# LEF file generated by Abstract Generator version 5.5.10 on Jul 28 14:07:14 2004
#
# Contains LEF for all bins.
# Options:   [x] Antenna
#            [x] Geometry
#            [x] Technology

VERSION 5.4 ;
NAMESCASESENSITIVE ON ;
BUSBITCHARS "[]" ;
DIVIDERCHAR "/" ;
UNITS
  DATABASE MICRONS 1000 ;
END UNITS

USEMINSPACING OBS ON ;
USEMINSPACING PIN OFF ;
CLEARANCEMEASURE EUCLIDEAN ;


MANUFACTURINGGRID 0.05 ;

LAYER nwell
  TYPE	MASTERSLICE ;
END nwell

LAYER nactive
  TYPE	MASTERSLICE ;
END nactive

LAYER pactive
  TYPE	MASTERSLICE ;
END pactive

LAYER poly
  TYPE	MASTERSLICE ;
END poly

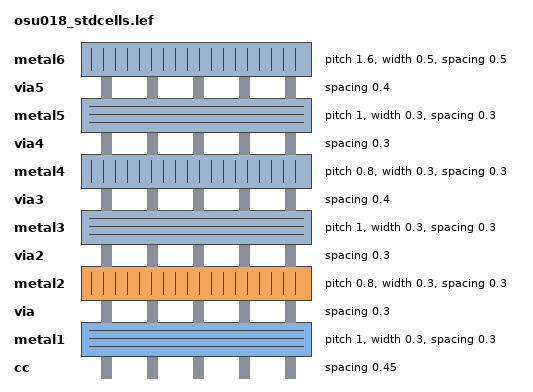
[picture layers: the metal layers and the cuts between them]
LAYER cc
  TYPE	CUT ;
  SPACING	0.45 ;
END cc

LAYER metal1
  TYPE		ROUTING ;
  DIRECTION	HORIZONTAL ;
  PITCH		1  ;
  OFFSET	0.5 ;
  WIDTH		0.3 ;
  SPACING	0.3 ;
  RESISTANCE	RPERSQ 0.08 ;
  CAPACITANCE	CPERSQDIST 3.8e-05 ;
  EDGECAPACITANCE 8.000000e-05 ;
END metal1

LAYER via
  TYPE	CUT ;
  SPACING	0.3 ;
END via

LAYER metal2
  TYPE		ROUTING ;
  DIRECTION	VERTICAL ;
  PITCH		0.8  ;
  OFFSET	0.4 ;
  WIDTH		0.3 ;
  SPACING	0.3 ;
  RESISTANCE	RPERSQ 0.08 ;
  CAPACITANCE	CPERSQDIST 1.9e-05 ;
  EDGECAPACITANCE 6.000000e-05 ;
END metal2

LAYER via2
  TYPE	CUT ;
  SPACING	0.3 ;
END via2

LAYER metal3
  TYPE		ROUTING ;
  DIRECTION	HORIZONTAL ;
  PITCH		1  ;
  OFFSET	0.5 ;
  WIDTH		0.3 ;
  SPACING	0.3 ;
  RESISTANCE	RPERSQ 0.08 ;
  CAPACITANCE	CPERSQDIST 1.3e-05 ;
  EDGECAPACITANCE 5.400000e-05 ;
END metal3

LAYER via3
  TYPE	CUT ;
  SPACING	0.4 ;
END via3

LAYER metal4
  TYPE		ROUTING ;
  DIRECTION	VERTICAL ;
  PITCH		0.8  ;
  OFFSET	0.4 ;
  WIDTH		0.3 ;
  SPACING	0.3 ;
  RESISTANCE	RPERSQ 0.07 ;
  CAPACITANCE	CPERSQDIST 8e-06 ;
  EDGECAPACITANCE 4.100000e-05 ;
END metal4

LAYER via4
  TYPE	CUT ;
  SPACING	0.3 ;
END via4

LAYER metal5
  TYPE		ROUTING ;
  DIRECTION	HORIZONTAL ;
  PITCH		1  ;
  OFFSET	0.5 ;
  WIDTH		0.3 ;
  SPACING	0.3 ;
  RESISTANCE	RPERSQ 0.07 ;
  CAPACITANCE	CPERSQDIST 8e-06 ;
  EDGECAPACITANCE 2.400000e-05 ;
END metal5

LAYER via5
  TYPE	CUT ;
  SPACING	0.4 ;
END via5

LAYER metal6
  TYPE		ROUTING ;
  DIRECTION	VERTICAL ;
  PITCH		1.6  ;
  OFFSET	0.8 ;
  WIDTH		0.5 ;
  SPACING	0.5 ;
  RESISTANCE	RPERSQ 0.03 ;
  CAPACITANCE	CPERSQDIST 3e-06 ;
  EDGECAPACITANCE 2.000000e-05 ;
END metal6

VIA M2_M1 DEFAULT
  LAYER metal1 ;
    RECT -0.200 -0.200 0.200 0.200 ;
  LAYER via ;
    RECT -0.100 -0.100 0.100 0.100 ;
  LAYER metal2 ;
    RECT -0.200 -0.200 0.200 0.200 ;
END M2_M1

VIA M3_M2 DEFAULT
  LAYER metal2 ;
    RECT -0.200 -0.200 0.200 0.200 ;
  LAYER via2 ;
    RECT -0.100 -0.100 0.100 0.100 ;
  LAYER metal3 ;
    RECT -0.200 -0.200 0.200 0.200 ;
END M3_M2

VIA M4_M3 DEFAULT
  LAYER metal3 ;
    RECT -0.200 -0.200 0.200 0.200 ;
  LAYER via3 ;
    RECT -0.100 -0.100 0.100 0.100 ;
  LAYER metal4 ;
    RECT -0.200 -0.200 0.200 0.200 ;
END M4_M3

VIA M5_M4 DEFAULT
  LAYER metal4 ;
    RECT -0.200 -0.200 0.200 0.200 ;
  LAYER via4 ;
    RECT -0.100 -0.100 0.100 0.100 ;
  LAYER metal5 ;
    RECT -0.200 -0.200 0.200 0.200 ;
END M5_M4

VIA M6_M5 DEFAULT
  LAYER metal5 ;
    RECT -0.25 -0.25 0.25 0.25 ;
  LAYER via5 ;
    RECT -0.15 -0.15 0.15 0.15 ;
  LAYER metal6 ;
    RECT -0.25 -0.25 0.25 0.25 ;
END M6_M5


VIARULE viagen21 GENERATE
  LAYER metal1 ;
    DIRECTION HORIZONTAL ;
    WIDTH 0.3 TO 60 ;
    OVERHANG 0.1 ;
    METALOVERHANG 0 ;
  LAYER metal2 ;
    DIRECTION VERTICAL ;
    WIDTH 0.3 TO 60 ;
    OVERHANG 0.1 ;
    METALOVERHANG 0 ;
  LAYER via ;
    RECT -0.1 -0.1 0.1 0.1 ;
    SPACING 0.5 BY 0.5 ;
END viagen21

VIARULE viagen32 GENERATE
  LAYER metal3 ;
    DIRECTION HORIZONTAL ;
    WIDTH 0.3 TO 60 ;
    OVERHANG 0.1 ;
    METALOVERHANG 0 ;
  LAYER metal2 ;
    DIRECTION VERTICAL ;
    WIDTH 0.3 TO 60 ;
    OVERHANG 0.1 ;
    METALOVERHANG 0 ;
  LAYER via2 ;
    RECT -0.1 -0.1 0.1 0.1 ;
    SPACING 0.5 BY 0.5 ;
END viagen32

VIARULE viagen43 GENERATE
  LAYER metal3 ;
    DIRECTION HORIZONTAL ;
    WIDTH 0.3 TO 60 ;
    OVERHANG 0.1 ;
    METALOVERHANG 0 ;
  LAYER metal4 ;
    DIRECTION VERTICAL ;
    WIDTH 0.3 TO 60 ;
    OVERHANG 0.1 ;
    METALOVERHANG 0 ;
  LAYER via3 ;
    RECT -0.1 -0.1 0.1 0.1 ;
    SPACING 0.6 BY 0.6 ;
END viagen43

VIARULE viagen54 GENERATE
  LAYER metal5 ;
    DIRECTION HORIZONTAL ;
    WIDTH 0.3 TO 60 ;
    OVERHANG 0.1 ;
    METALOVERHANG 0 ;
  LAYER metal4 ;
    DIRECTION VERTICAL ;
    WIDTH 0.3 TO 60 ;
    OVERHANG 0.1 ;
    METALOVERHANG 0 ;
  LAYER via4 ;
    RECT -0.1 -0.1 0.1 0.1 ;
    SPACING 0.5 BY 0.5 ;
END viagen54

VIARULE viagen65 GENERATE
  LAYER metal5 ;
    DIRECTION HORIZONTAL ;
    WIDTH 0.5 TO 60 ;
    OVERHANG 0.1 ;
    METALOVERHANG 0 ;
  LAYER metal6 ;
    DIRECTION VERTICAL ;
    WIDTH 0.5 TO 60 ;
    OVERHANG 0.1 ;
    METALOVERHANG 0 ;
  LAYER via5 ;
    RECT -0.15 -0.15 0.15 0.15 ;
    SPACING 0.7 BY 0.7 ;
END viagen65

VIARULE TURN1 GENERATE
  LAYER metal1 ;
    DIRECTION HORIZONTAL ;
  LAYER metal1 ;
    DIRECTION VERTICAL ;
END TURN1

VIARULE TURN2 GENERATE
  LAYER metal2 ;
    DIRECTION HORIZONTAL ;
  LAYER metal2 ;
    DIRECTION VERTICAL ;
END TURN2

VIARULE TURN3 GENERATE
  LAYER metal3 ;
    DIRECTION HORIZONTAL ;
  LAYER metal3 ;
    DIRECTION VERTICAL ;
END TURN3

VIARULE TURN4 GENERATE
  LAYER metal4 ;
    DIRECTION HORIZONTAL ;
  LAYER metal4 ;
    DIRECTION VERTICAL ;
END TURN4

VIARULE TURN5 GENERATE
  LAYER metal5 ;
    DIRECTION HORIZONTAL ;
  LAYER metal5 ;
    DIRECTION VERTICAL ;
END TURN5

VIARULE TURN6 GENERATE
  LAYER metal6 ;
    DIRECTION HORIZONTAL ;
  LAYER metal6 ;
    DIRECTION VERTICAL ;
END TURN6

SITE  core
    CLASS	CORE ;
    SYMMETRY	Y ;
    SIZE	0.800 BY 10.000 ;
END  core

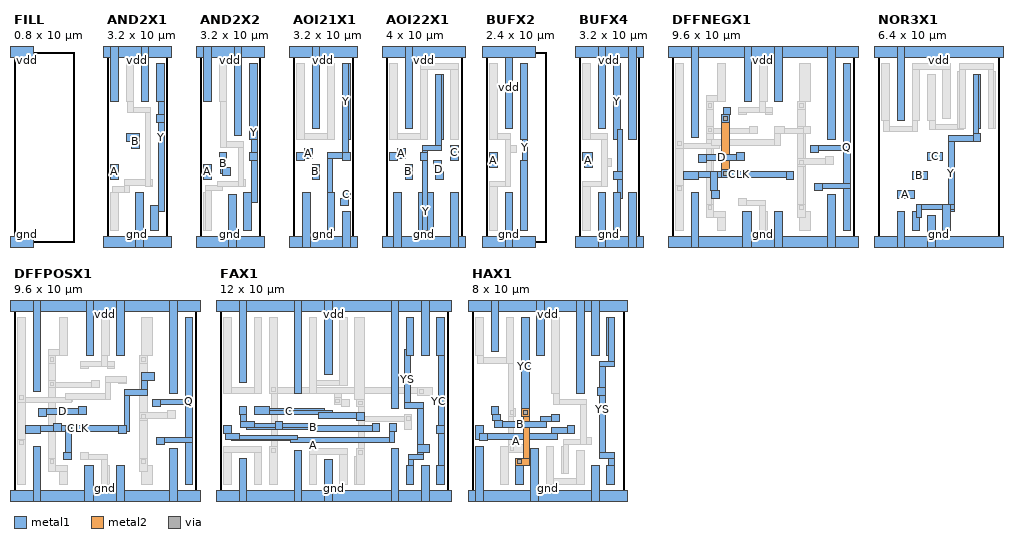
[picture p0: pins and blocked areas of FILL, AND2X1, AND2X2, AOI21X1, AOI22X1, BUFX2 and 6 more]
MACRO FILL
  CLASS  CORE ;
  FOREIGN FILL 0.000 0.000 ;
  ORIGIN 0.000 0.000 ;
  SIZE 0.800 BY 10.000 ;
  SYMMETRY X Y  ;
  SITE core ;
  PIN gnd
    DIRECTION INOUT ;
    USE GROUND ;
    SHAPE ABUTMENT ;
    PORT
      LAYER metal1 ;
        RECT -0.200 -0.300 1.000 0.300 ;
    END
  END gnd
  PIN vdd
    DIRECTION INOUT ;
    USE POWER ;
    SHAPE ABUTMENT ;
    PORT
      LAYER metal1 ;
        RECT -0.200 9.700 1.000 10.300 ;
    END
  END vdd
END FILL

MACRO AND2X1
  CLASS  CORE ;
  FOREIGN AND2X1 0.000 0.000 ;
  ORIGIN 0.000 0.000 ;
  SIZE 3.200 BY 10.000 ;
  SYMMETRY X Y  ;
  SITE core ;
  PIN A
    DIRECTION INPUT ;
    PORT
      LAYER metal1 ;
        RECT 0.200 3.300 0.600 4.100 ;
    END
  END A
  PIN B
    DIRECTION INPUT ;
    PORT
      LAYER metal1 ;
        RECT 1.300 4.900 1.700 5.700 ;
        RECT 1.000 5.300 1.700 5.700 ;
    END
  END B
  PIN gnd
    DIRECTION INOUT ;
    USE GROUND ;
    SHAPE ABUTMENT ;
    PORT
      LAYER metal1 ;
        RECT 1.500 -0.300 1.900 2.600 ;
        RECT -0.200 -0.300 3.400 0.300 ;
    END
  END gnd
  PIN Y
    DIRECTION OUTPUT ;
    PORT
      LAYER metal1 ;
        RECT 2.600 6.300 3.000 6.700 ;
        RECT 2.600 7.400 3.000 9.400 ;
        RECT 2.700 1.600 3.000 9.400 ;
        RECT 2.300 0.600 2.700 1.900 ;
    END
  END Y
  PIN vdd
    DIRECTION INOUT ;
    USE POWER ;
    SHAPE ABUTMENT ;
    PORT
      LAYER metal1 ;
        RECT 0.200 7.400 0.600 10.300 ;
        RECT -0.200 9.700 3.400 10.300 ;
        RECT 1.800 7.400 2.200 10.300 ;
    END
  END vdd
  OBS 
      LAYER metal1 ;
        RECT 0.200 0.600 0.600 2.600 ;
        RECT 0.300 2.600 1.200 2.900 ;
        RECT 0.900 2.600 1.200 3.300 ;
        RECT 2.000 2.900 2.400 3.300 ;
        RECT 0.900 3.000 2.400 3.300 ;
        RECT 2.000 2.900 2.300 7.100 ;
        RECT 1.100 6.800 2.300 7.100 ;
        RECT 1.100 6.800 1.400 9.400 ;
        RECT 1.000 7.400 1.400 9.400 ;
  END 
END AND2X1

MACRO AND2X2
  CLASS  CORE ;
  FOREIGN AND2X2 0.000 0.000 ;
  ORIGIN 0.000 0.000 ;
  SIZE 3.200 BY 10.000 ;
  SYMMETRY X Y  ;
  SITE core ;
  PIN A
    DIRECTION INPUT ;
    PORT
      LAYER metal1 ;
        RECT 0.200 3.300 0.600 4.100 ;
    END
  END A
  PIN B
    DIRECTION INPUT ;
    PORT
      LAYER metal1 ;
        RECT 1.100 3.600 1.400 4.700 ;
        RECT 1.200 3.500 1.600 3.900 ;
        RECT 1.000 4.300 1.400 4.700 ;
    END
  END B
  PIN gnd
    DIRECTION INOUT ;
    USE GROUND ;
    SHAPE ABUTMENT ;
    PORT
      LAYER metal1 ;
        RECT 1.500 -0.300 1.900 2.500 ;
        RECT -0.200 -0.300 3.400 0.300 ;
    END
  END gnd
  PIN Y
    DIRECTION OUTPUT ;
    PORT
      LAYER metal1 ;
        RECT 2.600 4.300 3.000 4.700 ;
        RECT 2.600 5.400 3.000 9.400 ;
        RECT 2.700 2.100 3.000 9.400 ;
        RECT 2.300 0.600 2.700 2.600 ;
    END
  END Y
  PIN vdd
    DIRECTION INOUT ;
    USE POWER ;
    SHAPE ABUTMENT ;
    PORT
      LAYER metal1 ;
        RECT 0.200 7.400 0.600 10.300 ;
        RECT -0.200 9.700 3.400 10.300 ;
        RECT 1.800 5.600 2.200 10.300 ;
    END
  END vdd
  OBS 
      LAYER metal1 ;
        RECT 0.200 0.600 0.600 2.600 ;
        RECT 0.300 0.600 0.600 3.000 ;
        RECT 0.300 2.700 1.200 3.000 ;
        RECT 0.900 2.900 2.400 3.200 ;
        RECT 2.000 2.900 2.400 3.300 ;
        RECT 2.000 2.900 2.300 5.300 ;
        RECT 1.100 5.000 2.300 5.300 ;
        RECT 1.100 5.000 1.400 9.400 ;
        RECT 1.000 7.400 1.400 9.400 ;
  END 
END AND2X2

MACRO AOI21X1
  CLASS  CORE ;
  FOREIGN AOI21X1 0.000 0.000 ;
  ORIGIN 0.000 0.000 ;
  SIZE 3.200 BY 10.000 ;
  SYMMETRY X Y  ;
  SITE core ;
  PIN A
    DIRECTION INPUT ;
    PORT
      LAYER metal1 ;
        RECT 0.200 4.300 0.600 4.700 ;
        RECT 0.600 4.400 1.000 4.900 ;
    END
  END A
  PIN B
    DIRECTION INPUT ;
    PORT
      LAYER metal1 ;
        RECT 1.000 3.300 1.400 4.100 ;
    END
  END B
  PIN C
    DIRECTION INPUT ;
    PORT
      LAYER metal1 ;
        RECT 2.500 1.900 2.900 2.300 ;
        RECT 2.600 2.300 3.000 2.700 ;
    END
  END C
  PIN gnd
    DIRECTION INOUT ;
    USE GROUND ;
    SHAPE ABUTMENT ;
    PORT
      LAYER metal1 ;
        RECT 0.500 -0.300 0.900 2.600 ;
        RECT -0.200 -0.300 3.400 0.300 ;
        RECT 2.600 -0.300 3.000 1.600 ;
    END
  END gnd
  PIN Y
    DIRECTION OUTPUT ;
    PORT
      LAYER metal1 ;
        RECT 1.800 0.600 2.100 4.700 ;
        RECT 2.600 5.400 3.000 9.400 ;
        RECT 1.800 4.400 3.000 4.700 ;
        RECT 2.600 4.300 3.000 4.700 ;
        RECT 2.600 4.300 2.900 9.400 ;
        RECT 1.800 0.600 2.200 2.600 ;
    END
  END Y
  PIN vdd
    DIRECTION INOUT ;
    USE POWER ;
    SHAPE ABUTMENT ;
    PORT
      LAYER metal1 ;
        RECT 1.000 6.000 1.400 10.300 ;
        RECT -0.200 9.700 3.400 10.300 ;
    END
  END vdd
  OBS 
      LAYER metal1 ;
        RECT 0.200 5.400 2.200 5.700 ;
        RECT 0.200 5.400 0.600 9.400 ;
        RECT 1.800 5.400 2.200 9.400 ;
  END 
END AOI21X1

MACRO AOI22X1
  CLASS  CORE ;
  FOREIGN AOI22X1 0.000 0.000 ;
  ORIGIN 0.000 0.000 ;
  SIZE 4.000 BY 10.000 ;
  SYMMETRY X Y  ;
  SITE core ;
  PIN A
    DIRECTION INPUT ;
    PORT
      LAYER metal1 ;
        RECT 0.200 4.300 0.600 4.700 ;
        RECT 0.600 4.400 1.000 4.900 ;
    END
  END A
  PIN B
    DIRECTION INPUT ;
    PORT
      LAYER metal1 ;
        RECT 1.000 3.300 1.400 4.100 ;
    END
  END B
  PIN C
    DIRECTION INPUT ;
    PORT
      LAYER metal1 ;
        RECT 3.400 4.300 3.800 5.100 ;
    END
  END C
  PIN D
    DIRECTION INPUT ;
    PORT
      LAYER metal1 ;
        RECT 2.600 3.300 2.900 4.300 ;
        RECT 2.600 3.300 3.000 3.700 ;
        RECT 2.500 3.900 2.900 4.300 ;
    END
  END D
  PIN gnd
    DIRECTION INOUT ;
    USE GROUND ;
    SHAPE ABUTMENT ;
    PORT
      LAYER metal1 ;
        RECT 0.400 -0.300 0.800 2.600 ;
        RECT -0.200 -0.300 4.200 0.300 ;
        RECT 3.400 -0.300 3.800 2.600 ;
    END
  END gnd
  PIN Y
    DIRECTION OUTPUT ;
    PORT
      LAYER metal1 ;
        RECT 1.800 4.300 2.200 4.700 ;
        RECT 2.600 5.400 3.000 8.800 ;
        RECT 2.600 4.800 2.900 8.800 ;
        RECT 1.900 4.800 2.900 5.100 ;
        RECT 1.700 0.600 2.500 2.600 ;
        RECT 1.900 0.600 2.200 5.100 ;
    END
  END Y
  PIN vdd
    DIRECTION INOUT ;
    USE POWER ;
    SHAPE ABUTMENT ;
    PORT
      LAYER metal1 ;
        RECT 1.000 6.000 1.400 10.300 ;
        RECT -0.200 9.700 4.200 10.300 ;
    END
  END vdd
  OBS 
      LAYER metal1 ;
        RECT 0.200 5.400 2.200 5.700 ;
        RECT 1.800 5.400 2.200 9.400 ;
        RECT 0.200 5.400 0.600 9.400 ;
        RECT 3.400 5.400 3.800 9.400 ;
        RECT 1.800 9.100 3.800 9.400 ;
  END 
END AOI22X1

MACRO BUFX2
  CLASS  CORE ;
  FOREIGN BUFX2 0.000 0.000 ;
  ORIGIN 0.000 0.000 ;
  SIZE 2.400 BY 10.000 ;
  SYMMETRY X Y  ;
  SITE core ;
  PIN A
    DIRECTION INPUT ;
    PORT
      LAYER metal1 ;
        RECT 0.200 3.900 0.600 4.700 ;
    END
  END A
  PIN gnd
    DIRECTION INOUT ;
    USE GROUND ;
    SHAPE ABUTMENT ;
    PORT
      LAYER metal1 ;
        RECT 1.000 -0.300 1.400 2.600 ;
        RECT -0.200 -0.300 2.600 0.300 ;
    END
  END gnd
  PIN Y
    DIRECTION OUTPUT ;
    PORT
      LAYER metal1 ;
        RECT 1.800 0.600 2.200 4.300 ;
        RECT 1.800 5.400 2.200 9.400 ;
        RECT 1.900 0.600 2.200 9.400 ;
    END
  END Y
  PIN vdd
    DIRECTION INOUT ;
    USE POWER ;
    SHAPE ABUTMENT ;
    PORT
      LAYER metal1 ;
        RECT 1.000 6.000 1.400 10.300 ;
        RECT -0.200 9.700 2.600 10.300 ;
    END
  END vdd
  OBS 
      LAYER metal1 ;
        RECT 0.200 0.600 0.600 3.200 ;
        RECT 0.200 2.900 1.300 3.200 ;
        RECT 1.000 4.700 1.600 5.100 ;
        RECT 1.000 2.900 1.300 5.700 ;
        RECT 0.200 5.400 1.300 5.700 ;
        RECT 0.200 5.400 0.600 9.400 ;
  END 
END BUFX2

MACRO BUFX4
  CLASS  CORE ;
  FOREIGN BUFX4 0.000 0.000 ;
  ORIGIN 0.000 0.000 ;
  SIZE 3.200 BY 10.000 ;
  SYMMETRY X Y  ;
  SITE core ;
  PIN A
    DIRECTION INPUT ;
    PORT
      LAYER metal1 ;
        RECT 0.300 3.900 0.700 4.700 ;
        RECT 0.200 4.300 0.700 4.700 ;
    END
  END A
  PIN gnd
    DIRECTION INOUT ;
    USE GROUND ;
    SHAPE ABUTMENT ;
    PORT
      LAYER metal1 ;
        RECT 1.000 -0.300 1.400 2.600 ;
        RECT -0.200 -0.300 3.400 0.300 ;
        RECT 2.600 -0.300 3.000 2.600 ;
    END
  END gnd
  PIN Y
    DIRECTION OUTPUT ;
    PORT
      LAYER metal1 ;
        RECT 1.800 0.600 2.200 2.600 ;
        RECT 2.000 2.300 2.300 5.900 ;
        RECT 1.800 5.400 2.200 9.400 ;
        RECT 1.800 3.300 2.300 3.700 ;
    END
  END Y
  PIN vdd
    DIRECTION INOUT ;
    USE POWER ;
    SHAPE ABUTMENT ;
    PORT
      LAYER metal1 ;
        RECT 1.000 6.000 1.400 10.300 ;
        RECT -0.200 9.700 3.400 10.300 ;
        RECT 2.600 5.400 3.000 10.300 ;
    END
  END vdd
  OBS 
      LAYER metal1 ;
        RECT 0.200 0.600 0.600 3.200 ;
        RECT 0.200 2.900 1.500 3.200 ;
        RECT 1.200 4.000 1.700 4.400 ;
        RECT 1.200 2.900 1.500 5.700 ;
        RECT 0.200 5.400 1.500 5.700 ;
        RECT 0.200 5.400 0.600 9.400 ;
  END 
END BUFX4

MACRO DFFNEGX1
  CLASS  CORE ;
  FOREIGN DFFNEGX1 0.000 0.000 ;
  ORIGIN 0.000 0.000 ;
  SIZE 9.600 BY 10.000 ;
  SYMMETRY X Y  ;
  SITE core ;
  PIN Q
    DIRECTION OUTPUT ;
    PORT
      LAYER metal1 ;
        RECT 7.300 4.700 7.700 5.100 ;
        RECT 9.000 0.600 9.400 9.400 ;
        RECT 7.300 4.800 9.400 5.100 ;
        RECT 7.500 2.800 9.400 3.100 ;
        RECT 7.500 2.700 7.900 3.100 ;
    END
  END Q
  PIN CLK
    DIRECTION INPUT ;
    USE CLOCK ;
    PORT
      LAYER metal2 ;
        RECT 2.600 3.400 3.000 6.700 ;
      LAYER via ;
        RECT 2.700 6.400 2.900 6.600 ;
        RECT 2.700 3.500 2.900 3.700 ;
      LAYER metal1 ;
        RECT 2.600 6.300 3.000 6.700 ;
        RECT 0.600 3.400 6.400 3.700 ;
        RECT 6.000 3.300 6.400 3.700 ;
        RECT 2.600 3.400 3.000 3.800 ;
        RECT 2.100 2.300 2.500 2.700 ;
        RECT 2.000 2.700 2.400 3.700 ;
        RECT 0.600 3.300 1.400 3.700 ;
        RECT 2.700 6.700 3.100 7.100 ;
    END
  END CLK
  PIN D
    DIRECTION INPUT ;
    PORT
      LAYER metal1 ;
        RECT 1.400 4.200 1.800 4.600 ;
        RECT 3.400 4.300 3.800 4.700 ;
        RECT 1.400 4.300 3.800 4.600 ;
    END
  END D
  PIN gnd
    DIRECTION INOUT ;
    USE GROUND ;
    SHAPE ABUTMENT ;
    PORT
      LAYER metal1 ;
        RECT 1.000 -0.300 1.400 2.600 ;
        RECT -0.200 -0.300 9.800 0.300 ;
        RECT 8.200 -0.300 8.600 2.500 ;
        RECT 5.400 -0.300 5.800 1.600 ;
        RECT 3.700 -0.300 4.200 1.600 ;
    END
  END gnd
  PIN vdd
    DIRECTION INOUT ;
    USE POWER ;
    SHAPE ABUTMENT ;
    PORT
      LAYER metal1 ;
        RECT 1.000 5.500 1.400 10.300 ;
        RECT -0.200 9.700 9.800 10.300 ;
        RECT 8.200 5.400 8.600 10.300 ;
        RECT 5.400 7.400 5.800 10.300 ;
        RECT 3.800 7.400 4.200 10.300 ;
    END
  END vdd
  OBS 
      LAYER metal2 ;
        RECT 0.200 2.600 0.600 5.400 ;
        RECT 1.800 1.600 2.200 5.000 ;
        RECT 1.800 1.600 2.100 7.400 ;
        RECT 1.800 5.400 2.200 7.400 ;
        RECT 6.600 1.600 7.000 5.700 ;
        RECT 6.600 1.600 6.900 7.400 ;
        RECT 6.600 6.100 7.000 7.400 ;
      LAYER metal1 ;
        RECT 0.200 0.600 0.600 3.000 ;
        RECT 1.800 7.000 2.200 7.700 ;
        RECT 1.800 7.400 2.800 7.700 ;
        RECT 2.400 7.400 2.800 9.400 ;
        RECT 2.400 0.600 2.800 1.600 ;
        RECT 1.800 1.300 2.800 1.600 ;
        RECT 1.800 1.300 2.200 2.000 ;
        RECT 1.800 5.700 4.500 6.000 ;
        RECT 1.800 5.700 2.200 6.100 ;
        RECT 4.100 5.700 4.500 6.100 ;
        RECT 4.600 0.600 5.000 1.600 ;
        RECT 4.600 0.600 4.900 2.200 ;
        RECT 3.500 1.900 4.900 2.200 ;
        RECT 3.500 1.900 3.900 2.300 ;
        RECT 3.500 6.700 3.900 7.100 ;
        RECT 4.900 6.700 5.300 7.100 ;
        RECT 3.500 6.800 5.300 7.100 ;
        RECT 4.600 6.800 4.900 9.400 ;
        RECT 4.600 7.400 5.000 9.400 ;
        RECT 6.600 7.000 7.000 7.400 ;
        RECT 6.700 7.400 7.300 9.400 ;
        RECT 0.200 4.900 2.500 5.200 ;
        RECT 2.100 5.100 5.700 5.400 ;
        RECT 5.400 5.100 5.700 6.100 ;
        RECT 5.400 5.700 7.300 6.000 ;
        RECT 5.400 5.700 5.900 6.100 ;
        RECT 6.900 5.700 7.300 6.100 ;
        RECT 0.200 4.900 0.600 9.400 ;
        RECT 6.700 0.600 7.300 1.600 ;
        RECT 6.600 1.300 7.000 2.000 ;
        RECT 6.600 4.000 7.000 4.400 ;
        RECT 6.600 4.100 8.500 4.400 ;
        RECT 8.100 4.100 8.500 4.500 ;
      LAYER via ;
        RECT 0.300 5.100 0.500 5.300 ;
        RECT 0.300 2.700 0.500 2.900 ;
        RECT 1.900 7.100 2.100 7.300 ;
        RECT 1.900 5.800 2.100 6.000 ;
        RECT 1.900 1.700 2.100 1.900 ;
        RECT 6.700 7.100 6.900 7.300 ;
        RECT 6.700 4.100 6.900 4.300 ;
        RECT 6.700 1.700 6.900 1.900 ;
  END 
END DFFNEGX1

MACRO NOR3X1
  CLASS  CORE ;
  FOREIGN NOR3X1 0.000 0.000 ;
  ORIGIN 0.000 0.000 ;
  SIZE 6.400 BY 10.000 ;
  SYMMETRY X Y  ;
  SITE core ;
  PIN A
    DIRECTION INPUT ;
    PORT
      LAYER metal1 ;
        RECT 1.000 2.300 1.900 2.700 ;
    END
  END A
  PIN B
    DIRECTION INPUT ;
    PORT
      LAYER metal1 ;
        RECT 1.800 3.300 2.600 3.700 ;
    END
  END B
  PIN C
    DIRECTION INPUT ;
    PORT
      LAYER metal1 ;
        RECT 2.600 4.300 3.400 4.700 ;
    END
  END C
  PIN gnd
    DIRECTION INOUT ;
    USE GROUND ;
    SHAPE ABUTMENT ;
    PORT
      LAYER metal1 ;
        RECT 1.000 -0.300 1.400 1.600 ;
        RECT -0.200 -0.300 6.600 0.300 ;
        RECT 2.600 -0.300 3.000 1.400 ;
    END
  END gnd
  PIN Y
    DIRECTION OUTPUT ;
    PORT
      LAYER metal1 ;
        RECT 1.800 0.600 2.200 1.600 ;
        RECT 5.000 6.000 5.400 8.800 ;
        RECT 5.000 5.300 5.400 5.700 ;
        RECT 5.000 5.300 5.300 8.800 ;
        RECT 3.700 5.300 5.400 5.600 ;
        RECT 3.700 1.600 4.000 5.600 ;
        RECT 3.400 0.600 3.800 2.000 ;
        RECT 2.000 1.700 4.000 2.000 ;
        RECT 2.000 1.300 2.300 2.000 ;
    END
  END Y
  PIN vdd
    DIRECTION INOUT ;
    USE POWER ;
    SHAPE ABUTMENT ;
    PORT
      LAYER metal1 ;
        RECT 1.000 6.400 1.400 10.300 ;
        RECT -0.200 9.700 6.600 10.300 ;
    END
  END vdd
  OBS 
      LAYER metal1 ;
        RECT 0.300 5.800 2.100 6.100 ;
        RECT 1.800 5.800 2.100 9.400 ;
        RECT 1.800 6.400 2.200 9.400 ;
        RECT 0.300 5.800 0.600 9.400 ;
        RECT 0.200 6.400 0.600 9.400 ;
        RECT 3.400 6.500 3.800 9.400 ;
        RECT 1.800 9.100 3.800 9.400 ;
        RECT 2.700 5.900 4.500 6.200 ;
        RECT 2.700 5.900 3.000 8.800 ;
        RECT 2.600 6.400 3.000 8.800 ;
        RECT 4.200 6.000 4.600 9.000 ;
        RECT 5.800 6.000 6.200 9.000 ;
        RECT 4.300 6.000 4.600 9.400 ;
        RECT 5.800 6.000 6.100 9.400 ;
        RECT 4.300 9.100 6.100 9.400 ;
  END 
END NOR3X1

MACRO DFFPOSX1
  CLASS  CORE ;
  FOREIGN DFFPOSX1 0.000 0.000 ;
  ORIGIN 0.000 0.000 ;
  SIZE 9.600 BY 10.000 ;
  SYMMETRY X Y  ;
  SITE core ;
  PIN Q
    DIRECTION OUTPUT ;
    PORT
      LAYER metal1 ;
        RECT 7.300 4.700 7.700 5.100 ;
        RECT 9.000 0.600 9.400 9.400 ;
        RECT 7.300 4.800 9.400 5.100 ;
        RECT 7.500 2.800 9.400 3.100 ;
        RECT 7.500 2.700 7.900 3.100 ;
    END
  END Q
  PIN CLK
    DIRECTION INPUT ;
    USE CLOCK ;
    PORT
      LAYER metal1 ;
        RECT 0.600 3.300 1.400 3.700 ;
        RECT 6.700 6.100 7.400 6.500 ;
        RECT 6.700 5.300 7.000 6.500 ;
        RECT 5.800 5.300 7.000 5.600 ;
        RECT 5.800 3.400 6.100 5.600 ;
        RECT 5.500 3.300 5.900 3.700 ;
        RECT 0.600 3.400 6.100 3.700 ;
        RECT 2.700 1.900 3.000 3.700 ;
        RECT 2.600 1.900 3.000 2.300 ;
        RECT 2.100 3.400 2.500 3.800 ;
    END
  END CLK
  PIN D
    DIRECTION INPUT ;
    PORT
      LAYER metal1 ;
        RECT 1.300 4.200 1.700 4.600 ;
        RECT 3.400 4.300 3.800 4.700 ;
        RECT 1.300 4.300 3.800 4.600 ;
    END
  END D
  PIN gnd
    DIRECTION INOUT ;
    USE GROUND ;
    SHAPE ABUTMENT ;
    PORT
      LAYER metal1 ;
        RECT 1.000 -0.300 1.400 2.600 ;
        RECT -0.200 -0.300 9.800 0.300 ;
        RECT 8.200 -0.300 8.600 2.500 ;
        RECT 5.400 -0.300 5.800 1.600 ;
        RECT 3.700 -0.300 4.200 1.600 ;
    END
  END gnd
  PIN vdd
    DIRECTION INOUT ;
    USE POWER ;
    SHAPE ABUTMENT ;
    PORT
      LAYER metal1 ;
        RECT 1.000 5.500 1.400 10.300 ;
        RECT -0.200 9.700 9.800 10.300 ;
        RECT 8.200 5.400 8.600 10.300 ;
        RECT 5.400 7.400 5.800 10.300 ;
        RECT 3.800 7.400 4.200 10.300 ;
    END
  END vdd
  OBS 
      LAYER metal2 ;
        RECT 0.200 2.600 0.600 5.400 ;
        RECT 1.800 1.600 2.200 7.400 ;
        RECT 6.600 1.600 7.000 7.400 ;
      LAYER metal1 ;
        RECT 0.200 0.600 0.600 3.000 ;
        RECT 1.800 7.000 2.200 7.700 ;
        RECT 1.800 7.400 2.800 7.700 ;
        RECT 2.400 7.400 2.800 9.400 ;
        RECT 2.400 0.600 2.800 1.600 ;
        RECT 1.800 1.300 2.800 1.600 ;
        RECT 1.800 1.300 2.200 2.000 ;
        RECT 1.800 5.700 4.500 6.000 ;
        RECT 1.800 5.700 2.200 6.100 ;
        RECT 4.100 5.700 4.500 6.100 ;
        RECT 4.600 0.600 5.000 1.600 ;
        RECT 4.600 0.600 4.900 2.200 ;
        RECT 3.500 1.900 4.900 2.200 ;
        RECT 3.500 1.900 3.900 2.300 ;
        RECT 3.500 6.700 3.900 7.100 ;
        RECT 4.900 6.700 5.300 7.100 ;
        RECT 3.500 6.800 5.300 7.100 ;
        RECT 4.600 6.800 4.900 9.400 ;
        RECT 4.600 7.400 5.000 9.400 ;
        RECT 0.200 5.000 3.100 5.200 ;
        RECT 0.200 4.900 3.000 5.200 ;
        RECT 2.700 5.100 5.100 5.400 ;
        RECT 4.800 5.100 5.100 6.300 ;
        RECT 5.500 5.900 5.900 6.300 ;
        RECT 4.800 6.000 5.900 6.300 ;
        RECT 0.200 4.900 0.600 9.400 ;
        RECT 6.600 7.000 7.000 7.400 ;
        RECT 6.700 7.400 7.300 9.400 ;
        RECT 6.700 0.600 7.300 1.600 ;
        RECT 6.600 1.300 7.000 2.000 ;
        RECT 6.600 4.000 7.000 4.400 ;
        RECT 6.600 4.100 8.500 4.400 ;
        RECT 8.100 4.100 8.500 4.500 ;
      LAYER via ;
        RECT 0.300 5.100 0.500 5.300 ;
        RECT 0.300 2.700 0.500 2.900 ;
        RECT 1.900 7.100 2.100 7.300 ;
        RECT 1.900 5.800 2.100 6.000 ;
        RECT 1.900 1.700 2.100 1.900 ;
        RECT 6.700 7.100 6.900 7.300 ;
        RECT 6.700 4.100 6.900 4.300 ;
        RECT 6.700 1.700 6.900 1.900 ;
  END 
END DFFPOSX1

MACRO FAX1
  CLASS  CORE ;
  FOREIGN FAX1 0.000 0.000 ;
  ORIGIN 0.000 0.000 ;
  SIZE 12.000 BY 10.000 ;
  SYMMETRY X Y  ;
  SITE core ;
  PIN YC
    DIRECTION OUTPUT ;
    PORT
      LAYER metal1 ;
        RECT 11.400 0.600 11.800 1.600 ;
        RECT 11.400 7.400 11.800 9.400 ;
        RECT 11.500 0.600 11.800 9.400 ;
        RECT 11.400 3.300 11.800 3.700 ;
    END
  END YC
  PIN YS
    DIRECTION OUTPUT ;
    PORT
      LAYER metal1 ;
        RECT 9.800 0.600 10.200 1.600 ;
        RECT 10.400 2.300 11.000 2.700 ;
        RECT 9.700 4.600 10.700 4.900 ;
        RECT 10.400 1.900 10.700 4.900 ;
        RECT 9.900 1.900 10.700 2.200 ;
        RECT 9.800 7.400 10.200 9.400 ;
        RECT 9.900 0.600 10.200 2.200 ;
        RECT 9.700 4.600 10.000 7.700 ;
    END
  END YS
  PIN A
    DIRECTION INPUT ;
    PORT
      LAYER metal1 ;
        RECT 0.300 3.000 1.000 3.300 ;
        RECT 8.900 3.400 9.300 3.800 ;
        RECT 8.900 2.800 9.200 3.800 ;
        RECT 3.700 2.800 9.200 3.100 ;
        RECT 0.300 3.000 4.100 3.200 ;
        RECT 0.600 2.900 9.200 3.100 ;
        RECT 0.200 3.300 0.600 3.700 ;
    END
  END A
  PIN B
    DIRECTION INPUT ;
    PORT
      LAYER metal1 ;
        RECT 1.100 3.600 1.400 4.700 ;
        RECT 8.000 3.400 8.400 3.800 ;
        RECT 4.700 3.400 8.400 3.700 ;
        RECT 1.100 3.600 5.100 3.800 ;
        RECT 1.400 3.500 8.400 3.700 ;
        RECT 2.900 3.500 3.300 3.900 ;
        RECT 1.100 3.600 1.800 3.900 ;
        RECT 1.000 4.300 1.400 4.700 ;
    END
  END B
  PIN C
    DIRECTION INPUT ;
    PORT
      LAYER metal1 ;
        RECT 1.800 4.300 2.600 4.700 ;
        RECT 7.200 4.000 7.600 4.400 ;
        RECT 5.200 4.100 7.600 4.400 ;
        RECT 1.800 4.300 5.900 4.500 ;
        RECT 1.800 4.300 5.500 4.600 ;
    END
  END C
  PIN gnd
    DIRECTION INOUT ;
    USE GROUND ;
    SHAPE ABUTMENT ;
    PORT
      LAYER metal1 ;
        RECT 1.000 -0.300 1.400 2.000 ;
        RECT -0.200 -0.300 12.200 0.300 ;
        RECT 10.600 -0.300 11.000 1.600 ;
        RECT 9.000 -0.300 9.400 2.500 ;
        RECT 5.500 -0.300 5.900 1.900 ;
        RECT 3.900 -0.300 4.300 2.400 ;
    END
  END gnd
  PIN vdd
    DIRECTION INOUT ;
    USE POWER ;
    SHAPE ABUTMENT ;
    PORT
      LAYER metal1 ;
        RECT 1.000 6.000 1.400 10.300 ;
        RECT -0.200 9.700 12.200 10.300 ;
        RECT 10.600 7.400 11.000 10.300 ;
        RECT 9.000 4.600 9.400 10.300 ;
        RECT 5.500 6.400 5.900 10.300 ;
        RECT 3.900 5.400 4.300 10.300 ;
    END
  END vdd
  OBS 
      LAYER metal2 ;
        RECT 7.200 2.100 7.600 2.500 ;
        RECT 7.300 3.900 10.100 4.200 ;
        RECT 9.700 3.900 10.100 4.300 ;
        RECT 7.300 2.100 7.600 5.100 ;
        RECT 7.200 4.700 7.600 5.100 ;
        RECT 2.600 2.200 3.000 2.600 ;
        RECT 6.000 4.800 6.400 5.700 ;
        RECT 10.400 5.300 10.800 5.700 ;
        RECT 2.600 5.400 10.800 5.700 ;
        RECT 2.700 2.200 3.000 5.800 ;
        RECT 2.600 5.400 3.000 5.800 ;
      LAYER metal1 ;
        RECT 0.200 5.400 2.200 5.700 ;
        RECT 0.200 5.400 0.600 9.400 ;
        RECT 1.800 5.400 2.200 9.400 ;
        RECT 0.200 0.600 0.600 2.600 ;
        RECT 1.800 0.600 2.200 2.600 ;
        RECT 0.200 2.300 2.200 2.600 ;
        RECT 2.600 5.400 3.000 9.400 ;
        RECT 2.600 0.600 3.000 2.600 ;
        RECT 4.700 5.800 6.700 6.100 ;
        RECT 4.700 5.400 5.100 9.400 ;
        RECT 6.300 5.800 6.700 9.400 ;
        RECT 4.700 0.600 5.100 2.500 ;
        RECT 6.300 0.600 6.700 2.500 ;
        RECT 4.700 2.200 6.700 2.500 ;
        RECT 6.400 4.700 6.800 5.100 ;
        RECT 6.000 4.800 6.400 5.200 ;
        RECT 7.200 4.700 7.600 9.400 ;
        RECT 7.100 5.100 7.600 9.400 ;
        RECT 7.100 0.600 7.600 2.100 ;
        RECT 7.200 0.600 7.600 2.500 ;
        RECT 9.700 3.500 10.100 4.300 ;
        RECT 10.400 5.300 11.200 5.700 ;
      LAYER via ;
        RECT 2.700 5.500 2.900 5.700 ;
        RECT 2.700 2.300 2.900 2.500 ;
        RECT 6.100 4.900 6.300 5.100 ;
        RECT 7.300 4.800 7.500 5.000 ;
        RECT 7.300 2.200 7.500 2.400 ;
        RECT 9.800 4.000 10.000 4.200 ;
        RECT 10.500 5.400 10.700 5.600 ;
  END 
END FAX1

MACRO HAX1
  CLASS  CORE ;
  FOREIGN HAX1 0.000 0.000 ;
  ORIGIN 0.000 0.000 ;
  SIZE 8.000 BY 10.000 ;
  SYMMETRY X Y  ;
  SITE core ;
  PIN YC
    DIRECTION OUTPUT ;
    PORT
      LAYER metal2 ;
        RECT 2.300 1.600 3.000 2.000 ;
        RECT 2.600 4.200 3.000 4.600 ;
        RECT 2.700 1.600 3.000 4.600 ;
      LAYER via ;
        RECT 2.400 1.700 2.600 1.900 ;
        RECT 2.700 4.300 2.900 4.500 ;
      LAYER metal1 ;
        RECT 2.300 0.600 2.700 2.000 ;
        RECT 2.600 4.200 3.000 9.400 ;
    END
  END YC
  PIN YS
    DIRECTION OUTPUT ;
    PORT
      LAYER metal1 ;
        RECT 6.600 5.300 7.000 5.700 ;
        RECT 7.100 7.400 7.500 9.400 ;
        RECT 7.200 6.800 7.500 9.400 ;
        RECT 6.700 2.000 7.500 2.300 ;
        RECT 7.200 0.600 7.500 2.300 ;
        RECT 6.700 6.800 7.500 7.100 ;
        RECT 7.100 0.600 7.500 1.600 ;
        RECT 6.700 2.000 7.000 7.100 ;
    END
  END YS
  PIN A
    DIRECTION INPUT ;
    PORT
      LAYER metal1 ;
        RECT 0.200 3.000 0.600 3.700 ;
        RECT 5.000 3.300 5.400 3.700 ;
        RECT 4.200 3.300 5.400 3.600 ;
        RECT 0.200 3.000 4.500 3.300 ;
        RECT 0.400 2.900 0.800 3.300 ;
    END
  END A
  PIN B
    DIRECTION INPUT ;
    PORT
      LAYER metal1 ;
        RECT 1.100 4.000 1.500 4.300 ;
        RECT 4.200 3.900 4.600 4.300 ;
        RECT 3.600 3.900 4.600 4.200 ;
        RECT 1.200 3.600 3.900 3.900 ;
        RECT 1.200 3.600 1.600 4.000 ;
        RECT 1.000 4.300 1.400 4.700 ;
    END
  END B
  PIN gnd
    DIRECTION INOUT ;
    USE GROUND ;
    SHAPE ABUTMENT ;
    PORT
      LAYER metal1 ;
        RECT 0.200 -0.300 0.600 2.600 ;
        RECT -0.200 -0.300 8.200 0.300 ;
        RECT 6.300 -0.300 6.700 1.600 ;
        RECT 3.100 -0.300 3.500 2.500 ;
    END
  END gnd
  PIN vdd
    DIRECTION INOUT ;
    USE POWER ;
    SHAPE ABUTMENT ;
    PORT
      LAYER metal1 ;
        RECT 1.000 7.600 1.400 10.300 ;
        RECT -0.200 9.700 8.200 10.300 ;
        RECT 6.300 7.400 6.700 10.300 ;
        RECT 5.500 5.400 5.900 10.300 ;
        RECT 3.400 7.400 3.800 10.300 ;
    END
  END vdd
  OBS 
      LAYER metal2 ;
        RECT 1.900 2.300 2.300 2.700 ;
        RECT 1.900 2.300 2.200 4.600 ;
        RECT 1.900 4.200 2.300 4.600 ;
      LAYER metal1 ;
        RECT 1.900 4.200 2.300 4.600 ;
        RECT 0.300 7.000 2.200 7.300 ;
        RECT 0.300 7.000 0.600 9.400 ;
        RECT 0.200 7.400 0.600 9.400 ;
        RECT 1.900 4.200 2.200 9.400 ;
        RECT 1.800 7.000 2.200 9.400 ;
        RECT 1.500 0.600 1.900 2.600 ;
        RECT 1.900 2.300 2.800 2.700 ;
        RECT 3.900 0.600 5.900 0.900 ;
        RECT 5.500 0.600 5.900 2.400 ;
        RECT 3.900 0.600 4.300 2.600 ;
        RECT 4.700 1.200 5.100 2.600 ;
        RECT 4.800 1.200 5.100 3.000 ;
        RECT 4.800 2.700 6.300 3.000 ;
        RECT 5.700 2.700 6.300 3.100 ;
        RECT 5.700 2.700 6.000 5.100 ;
        RECT 4.300 4.800 6.000 5.100 ;
        RECT 4.300 4.800 4.600 9.400 ;
        RECT 4.200 5.400 4.600 9.400 ;
      LAYER via ;
        RECT 2.000 4.300 2.200 4.500 ;
        RECT 2.000 2.400 2.200 2.600 ;
  END 
END HAX1

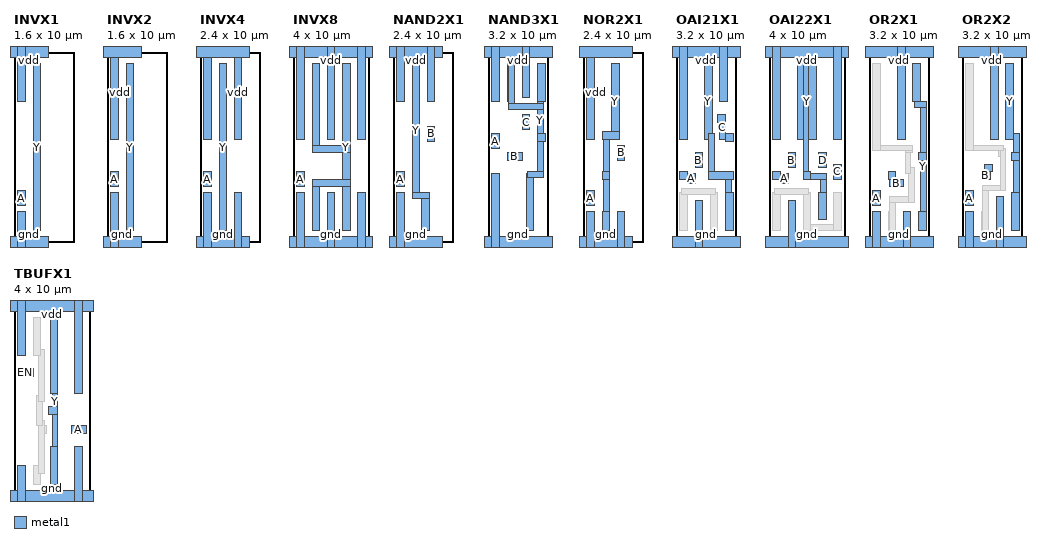
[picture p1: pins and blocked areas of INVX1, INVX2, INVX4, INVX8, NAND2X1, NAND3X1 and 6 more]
MACRO INVX1
  CLASS  CORE ;
  FOREIGN INVX1 0.000 0.000 ;
  ORIGIN 0.000 0.000 ;
  SIZE 1.600 BY 10.000 ;
  SYMMETRY X Y  ;
  SITE core ;
  PIN A
    DIRECTION INPUT ;
    PORT
      LAYER metal1 ;
        RECT 0.200 1.900 0.600 2.700 ;
    END
  END A
  PIN gnd
    DIRECTION INOUT ;
    USE GROUND ;
    SHAPE ABUTMENT ;
    PORT
      LAYER metal1 ;
        RECT 0.200 -0.300 0.600 1.600 ;
        RECT -0.200 -0.300 1.800 0.300 ;
    END
  END gnd
  PIN Y
    DIRECTION OUTPUT ;
    PORT
      LAYER metal1 ;
        RECT 1.000 0.600 1.400 9.400 ;
    END
  END Y
  PIN vdd
    DIRECTION INOUT ;
    USE POWER ;
    SHAPE ABUTMENT ;
    PORT
      LAYER metal1 ;
        RECT 0.200 7.400 0.600 10.300 ;
        RECT -0.200 9.700 1.800 10.300 ;
    END
  END vdd
END INVX1

MACRO INVX2
  CLASS  CORE ;
  FOREIGN INVX2 0.000 0.000 ;
  ORIGIN 0.000 0.000 ;
  SIZE 1.600 BY 10.000 ;
  SYMMETRY X Y  ;
  SITE core ;
  PIN A
    DIRECTION INPUT ;
    PORT
      LAYER metal1 ;
        RECT 0.200 2.900 0.600 3.700 ;
    END
  END A
  PIN gnd
    DIRECTION INOUT ;
    USE GROUND ;
    SHAPE ABUTMENT ;
    PORT
      LAYER metal1 ;
        RECT 0.200 -0.300 0.600 2.600 ;
        RECT -0.200 -0.300 1.800 0.300 ;
    END
  END gnd
  PIN Y
    DIRECTION OUTPUT ;
    PORT
      LAYER metal1 ;
        RECT 1.000 0.600 1.400 9.400 ;
    END
  END Y
  PIN vdd
    DIRECTION INOUT ;
    USE POWER ;
    SHAPE ABUTMENT ;
    PORT
      LAYER metal1 ;
        RECT 0.200 5.400 0.600 10.300 ;
        RECT -0.200 9.700 1.800 10.300 ;
    END
  END vdd
END INVX2

MACRO INVX4
  CLASS  CORE ;
  FOREIGN INVX4 0.000 0.000 ;
  ORIGIN 0.000 0.000 ;
  SIZE 2.400 BY 10.000 ;
  SYMMETRY X Y  ;
  SITE core ;
  PIN A
    DIRECTION INPUT ;
    PORT
      LAYER metal1 ;
        RECT 0.200 2.900 0.600 3.700 ;
    END
  END A
  PIN gnd
    DIRECTION INOUT ;
    USE GROUND ;
    SHAPE ABUTMENT ;
    PORT
      LAYER metal1 ;
        RECT 0.200 -0.300 0.600 2.600 ;
        RECT -0.200 -0.300 2.600 0.300 ;
        RECT 1.800 -0.300 2.200 2.600 ;
    END
  END gnd
  PIN Y
    DIRECTION OUTPUT ;
    PORT
      LAYER metal1 ;
        RECT 1.000 0.600 1.400 9.400 ;
    END
  END Y
  PIN vdd
    DIRECTION INOUT ;
    USE POWER ;
    SHAPE ABUTMENT ;
    PORT
      LAYER metal1 ;
        RECT 0.200 5.400 0.600 10.300 ;
        RECT -0.200 9.700 2.600 10.300 ;
        RECT 1.800 5.400 2.200 10.300 ;
    END
  END vdd
END INVX4

MACRO INVX8
  CLASS  CORE ;
  FOREIGN INVX8 0.000 0.000 ;
  ORIGIN 0.000 0.000 ;
  SIZE 4.000 BY 10.000 ;
  SYMMETRY X Y  ;
  SITE core ;
  PIN A
    DIRECTION INPUT ;
    PORT
      LAYER metal1 ;
        RECT 0.200 2.900 0.600 3.700 ;
    END
  END A
  PIN gnd
    DIRECTION INOUT ;
    USE GROUND ;
    SHAPE ABUTMENT ;
    PORT
      LAYER metal1 ;
        RECT 0.200 -0.300 0.600 2.600 ;
        RECT -0.200 -0.300 4.200 0.300 ;
        RECT 3.400 -0.300 3.800 2.600 ;
        RECT 1.800 -0.300 2.200 2.600 ;
    END
  END gnd
  PIN Y
    DIRECTION OUTPUT ;
    PORT
      LAYER metal1 ;
        RECT 1.000 0.600 1.400 3.300 ;
        RECT 2.600 0.600 3.000 9.400 ;
        RECT 1.000 4.700 3.000 5.100 ;
        RECT 1.000 2.900 3.000 3.300 ;
        RECT 1.000 4.700 1.400 9.400 ;
    END
  END Y
  PIN vdd
    DIRECTION INOUT ;
    USE POWER ;
    SHAPE ABUTMENT ;
    PORT
      LAYER metal1 ;
        RECT 0.200 5.400 0.600 10.300 ;
        RECT -0.200 9.700 4.200 10.300 ;
        RECT 3.400 5.400 3.800 10.300 ;
        RECT 1.800 5.400 2.200 10.300 ;
    END
  END vdd
END INVX8

MACRO NAND2X1
  CLASS  CORE ;
  FOREIGN NAND2X1 0.000 0.000 ;
  ORIGIN 0.000 0.000 ;
  SIZE 2.400 BY 10.000 ;
  SYMMETRY X Y  ;
  SITE core ;
  PIN A
    DIRECTION INPUT ;
    PORT
      LAYER metal1 ;
        RECT 0.200 2.900 0.600 3.700 ;
    END
  END A
  PIN B
    DIRECTION INPUT ;
    PORT
      LAYER metal1 ;
        RECT 1.800 5.300 2.200 6.100 ;
    END
  END B
  PIN gnd
    DIRECTION INOUT ;
    USE GROUND ;
    SHAPE ABUTMENT ;
    PORT
      LAYER metal1 ;
        RECT 0.200 -0.300 0.600 2.600 ;
        RECT -0.200 -0.300 2.600 0.300 ;
    END
  END gnd
  PIN Y
    DIRECTION OUTPUT ;
    PORT
      LAYER metal1 ;
        RECT 1.000 2.300 1.400 9.400 ;
        RECT 1.000 2.300 1.900 2.600 ;
        RECT 1.500 0.600 1.900 2.600 ;
    END
  END Y
  PIN vdd
    DIRECTION INOUT ;
    USE POWER ;
    SHAPE ABUTMENT ;
    PORT
      LAYER metal1 ;
        RECT 0.200 7.400 0.600 10.300 ;
        RECT -0.200 9.700 2.600 10.300 ;
        RECT 1.800 7.400 2.200 10.300 ;
    END
  END vdd
END NAND2X1

MACRO NAND3X1
  CLASS  CORE ;
  FOREIGN NAND3X1 0.000 0.000 ;
  ORIGIN 0.000 0.000 ;
  SIZE 3.200 BY 10.000 ;
  SYMMETRY X Y  ;
  SITE core ;
  PIN A
    DIRECTION INPUT ;
    PORT
      LAYER metal1 ;
        RECT 0.200 4.900 0.600 5.700 ;
    END
  END A
  PIN B
    DIRECTION INPUT ;
    PORT
      LAYER metal1 ;
        RECT 1.000 4.300 1.800 4.700 ;
    END
  END B
  PIN C
    DIRECTION INPUT ;
    PORT
      LAYER metal1 ;
        RECT 1.800 5.900 2.200 6.700 ;
    END
  END C
  PIN gnd
    DIRECTION INOUT ;
    USE GROUND ;
    SHAPE ABUTMENT ;
    PORT
      LAYER metal1 ;
        RECT 0.200 -0.300 0.600 3.600 ;
        RECT -0.200 -0.300 3.400 0.300 ;
    END
  END gnd
  PIN Y
    DIRECTION OUTPUT ;
    PORT
      LAYER metal1 ;
        RECT 1.100 7.000 1.400 9.400 ;
        RECT 2.600 7.400 3.000 9.400 ;
        RECT 2.600 5.300 3.000 5.700 ;
        RECT 2.600 3.400 2.900 9.400 ;
        RECT 1.100 7.000 2.900 7.300 ;
        RECT 2.100 3.400 2.900 3.700 ;
        RECT 2.000 0.600 2.400 3.600 ;
        RECT 1.000 7.400 1.400 9.400 ;
    END
  END Y
  PIN vdd
    DIRECTION INOUT ;
    USE POWER ;
    SHAPE ABUTMENT ;
    PORT
      LAYER metal1 ;
        RECT 0.200 7.400 0.600 10.300 ;
        RECT -0.200 9.700 3.400 10.300 ;
        RECT 1.800 7.600 2.200 10.300 ;
    END
  END vdd
END NAND3X1

MACRO NOR2X1
  CLASS  CORE ;
  FOREIGN NOR2X1 0.000 0.000 ;
  ORIGIN 0.000 0.000 ;
  SIZE 2.400 BY 10.000 ;
  SYMMETRY X Y  ;
  SITE core ;
  PIN A
    DIRECTION INPUT ;
    PORT
      LAYER metal1 ;
        RECT 0.200 1.900 0.600 2.700 ;
    END
  END A
  PIN B
    DIRECTION INPUT ;
    PORT
      LAYER metal1 ;
        RECT 1.800 4.300 2.200 5.100 ;
    END
  END B
  PIN gnd
    DIRECTION INOUT ;
    USE GROUND ;
    SHAPE ABUTMENT ;
    PORT
      LAYER metal1 ;
        RECT 0.200 -0.300 0.600 1.600 ;
        RECT -0.200 -0.300 2.600 0.300 ;
        RECT 1.800 -0.300 2.200 1.600 ;
    END
  END gnd
  PIN Y
    DIRECTION OUTPUT ;
    PORT
      LAYER metal1 ;
        RECT 1.000 0.600 1.400 1.600 ;
        RECT 1.500 5.400 1.900 9.400 ;
        RECT 1.000 5.400 1.900 5.800 ;
        RECT 1.100 0.600 1.400 5.800 ;
        RECT 1.000 3.300 1.400 3.700 ;
    END
  END Y
  PIN vdd
    DIRECTION INOUT ;
    USE POWER ;
    SHAPE ABUTMENT ;
    PORT
      LAYER metal1 ;
        RECT 0.200 5.400 0.600 10.300 ;
        RECT -0.200 9.700 2.600 10.300 ;
    END
  END vdd
END NOR2X1

MACRO OAI21X1
  CLASS  CORE ;
  FOREIGN OAI21X1 0.000 0.000 ;
  ORIGIN 0.000 0.000 ;
  SIZE 3.200 BY 10.000 ;
  SYMMETRY X Y  ;
  SITE core ;
  PIN A
    DIRECTION INPUT ;
    PORT
      LAYER metal1 ;
        RECT 0.200 3.300 0.600 3.700 ;
        RECT 0.600 3.100 1.000 3.600 ;
    END
  END A
  PIN B
    DIRECTION INPUT ;
    PORT
      LAYER metal1 ;
        RECT 1.000 3.900 1.400 4.700 ;
    END
  END B
  PIN C
    DIRECTION INPUT ;
    PORT
      LAYER metal1 ;
        RECT 2.300 5.400 2.600 6.700 ;
        RECT 2.600 5.300 3.000 5.700 ;
        RECT 2.200 6.300 2.600 6.700 ;
    END
  END C
  PIN gnd
    DIRECTION INOUT ;
    USE GROUND ;
    SHAPE ABUTMENT ;
    PORT
      LAYER metal1 ;
        RECT 1.000 -0.300 1.400 2.200 ;
        RECT -0.200 -0.300 3.400 0.300 ;
    END
  END gnd
  PIN Y
    DIRECTION OUTPUT ;
    PORT
      LAYER metal1 ;
        RECT 1.500 5.400 1.900 9.400 ;
        RECT 1.700 3.300 3.000 3.700 ;
        RECT 2.600 0.600 3.000 2.600 ;
        RECT 2.600 0.600 2.900 3.700 ;
        RECT 1.700 3.300 2.000 5.700 ;
    END
  END Y
  PIN vdd
    DIRECTION INOUT ;
    USE POWER ;
    SHAPE ABUTMENT ;
    PORT
      LAYER metal1 ;
        RECT 0.200 5.400 0.600 10.300 ;
        RECT -0.200 9.700 3.400 10.300 ;
        RECT 2.300 7.400 2.700 10.300 ;
    END
  END vdd
  OBS 
      LAYER metal1 ;
        RECT 0.200 0.600 0.600 2.600 ;
        RECT 1.800 0.600 2.200 2.600 ;
        RECT 0.300 2.500 2.100 2.800 ;
  END 
END OAI21X1

MACRO OAI22X1
  CLASS  CORE ;
  FOREIGN OAI22X1 0.000 0.000 ;
  ORIGIN 0.000 0.000 ;
  SIZE 4.000 BY 10.000 ;
  SYMMETRY X Y  ;
  SITE core ;
  PIN A
    DIRECTION INPUT ;
    PORT
      LAYER metal1 ;
        RECT 0.200 3.300 0.600 3.700 ;
        RECT 0.600 3.100 1.000 3.600 ;
    END
  END A
  PIN B
    DIRECTION INPUT ;
    PORT
      LAYER metal1 ;
        RECT 1.000 3.900 1.400 4.700 ;
    END
  END B
  PIN C
    DIRECTION INPUT ;
    PORT
      LAYER metal1 ;
        RECT 3.400 3.300 3.800 4.100 ;
    END
  END C
  PIN D
    DIRECTION INPUT ;
    PORT
      LAYER metal1 ;
        RECT 2.600 3.900 3.000 4.700 ;
    END
  END D
  PIN gnd
    DIRECTION INOUT ;
    USE GROUND ;
    SHAPE ABUTMENT ;
    PORT
      LAYER metal1 ;
        RECT 1.000 -0.300 1.400 2.200 ;
        RECT -0.200 -0.300 4.200 0.300 ;
    END
  END gnd
  PIN Y
    DIRECTION OUTPUT ;
    PORT
      LAYER metal1 ;
        RECT 1.800 3.300 2.100 9.400 ;
        RECT 1.800 3.300 3.000 3.600 ;
        RECT 2.700 1.200 3.000 3.600 ;
        RECT 2.600 1.200 3.000 2.600 ;
        RECT 1.500 5.400 2.500 9.400 ;
        RECT 1.800 3.300 2.200 3.700 ;
    END
  END Y
  PIN vdd
    DIRECTION INOUT ;
    USE POWER ;
    SHAPE ABUTMENT ;
    PORT
      LAYER metal1 ;
        RECT 0.200 5.400 0.600 10.300 ;
        RECT -0.200 9.700 4.200 10.300 ;
        RECT 3.400 5.400 3.800 10.300 ;
    END
  END vdd
  OBS 
      LAYER metal1 ;
        RECT 1.800 0.600 3.800 0.900 ;
        RECT 0.200 0.600 0.600 2.600 ;
        RECT 1.800 0.600 2.200 2.600 ;
        RECT 3.400 0.600 3.800 2.600 ;
        RECT 0.300 2.500 2.100 2.800 ;
  END 
END OAI22X1

MACRO OR2X1
  CLASS  CORE ;
  FOREIGN OR2X1 0.000 0.000 ;
  ORIGIN 0.000 0.000 ;
  SIZE 3.200 BY 10.000 ;
  SYMMETRY X Y  ;
  SITE core ;
  PIN A
    DIRECTION INPUT ;
    PORT
      LAYER metal1 ;
        RECT 0.200 1.900 0.600 2.700 ;
    END
  END A
  PIN B
    DIRECTION INPUT ;
    PORT
      LAYER metal1 ;
        RECT 1.000 3.300 1.400 3.700 ;
        RECT 1.100 2.900 1.800 3.300 ;
    END
  END B
  PIN gnd
    DIRECTION INOUT ;
    USE GROUND ;
    SHAPE ABUTMENT ;
    PORT
      LAYER metal1 ;
        RECT 0.200 -0.300 0.600 1.600 ;
        RECT -0.200 -0.300 3.400 0.300 ;
        RECT 1.800 -0.300 2.200 1.600 ;
    END
  END gnd
  PIN Y
    DIRECTION OUTPUT ;
    PORT
      LAYER metal1 ;
        RECT 2.600 0.600 3.000 1.600 ;
        RECT 2.700 0.600 3.000 7.400 ;
        RECT 2.300 7.400 2.700 9.400 ;
        RECT 2.400 7.100 3.000 7.400 ;
        RECT 2.600 4.300 3.000 4.700 ;
    END
  END Y
  PIN vdd
    DIRECTION INOUT ;
    USE POWER ;
    SHAPE ABUTMENT ;
    PORT
      LAYER metal1 ;
        RECT 1.500 5.400 1.900 10.300 ;
        RECT -0.200 9.700 3.400 10.300 ;
    END
  END vdd
  OBS 
      LAYER metal1 ;
        RECT 1.000 0.600 1.400 1.600 ;
        RECT 1.100 0.600 1.400 2.400 ;
        RECT 1.100 2.100 2.400 2.400 ;
        RECT 2.100 2.100 2.400 3.900 ;
        RECT 1.900 3.600 2.200 5.100 ;
        RECT 1.900 4.700 2.300 5.100 ;
        RECT 0.200 4.800 2.300 5.100 ;
        RECT 0.200 4.800 0.600 9.400 ;
  END 
END OR2X1

MACRO OR2X2
  CLASS  CORE ;
  FOREIGN OR2X2 0.000 0.000 ;
  ORIGIN 0.000 0.000 ;
  SIZE 3.200 BY 10.000 ;
  SYMMETRY X Y  ;
  SITE core ;
  PIN A
    DIRECTION INPUT ;
    PORT
      LAYER metal1 ;
        RECT 0.200 1.900 0.600 2.700 ;
    END
  END A
  PIN B
    DIRECTION INPUT ;
    PORT
      LAYER metal1 ;
        RECT 1.000 3.300 1.500 3.700 ;
        RECT 1.200 3.700 1.600 4.100 ;
    END
  END B
  PIN gnd
    DIRECTION INOUT ;
    USE GROUND ;
    SHAPE ABUTMENT ;
    PORT
      LAYER metal1 ;
        RECT 0.200 -0.300 0.600 1.600 ;
        RECT -0.200 -0.300 3.400 0.300 ;
        RECT 1.800 -0.300 2.200 2.400 ;
    END
  END gnd
  PIN Y
    DIRECTION OUTPUT ;
    PORT
      LAYER metal1 ;
        RECT 2.600 0.600 3.000 2.600 ;
        RECT 2.700 0.600 3.000 5.700 ;
        RECT 2.300 5.400 2.700 9.400 ;
        RECT 2.600 4.300 3.000 4.700 ;
    END
  END Y
  PIN vdd
    DIRECTION INOUT ;
    USE POWER ;
    SHAPE ABUTMENT ;
    PORT
      LAYER metal1 ;
        RECT 1.500 5.400 1.900 10.300 ;
        RECT -0.200 9.700 3.400 10.300 ;
    END
  END vdd
  OBS 
      LAYER metal1 ;
        RECT 1.000 0.600 1.400 1.600 ;
        RECT 1.100 0.600 1.400 3.000 ;
        RECT 1.100 2.700 2.300 3.000 ;
        RECT 1.900 4.500 2.300 4.900 ;
        RECT 2.000 2.700 2.300 4.900 ;
        RECT 0.200 4.800 2.200 5.100 ;
        RECT 0.200 4.800 0.600 9.400 ;
  END 
END OR2X2

MACRO TBUFX1
  CLASS  CORE ;
  FOREIGN TBUFX1 0.000 0.000 ;
  ORIGIN 0.000 0.000 ;
  SIZE 4.000 BY 10.000 ;
  SYMMETRY X Y  ;
  SITE core ;
  PIN A
    DIRECTION INPUT ;
    PORT
      LAYER metal1 ;
        RECT 3.000 3.300 3.800 3.700 ;
    END
  END A
  PIN EN
    DIRECTION INPUT ;
    PORT
      LAYER metal1 ;
        RECT 0.200 6.300 1.000 6.700 ;
    END
  END EN
  PIN gnd
    DIRECTION INOUT ;
    USE GROUND ;
    SHAPE ABUTMENT ;
    PORT
      LAYER metal1 ;
        RECT 0.200 -0.300 0.600 1.600 ;
        RECT -0.200 -0.300 4.200 0.300 ;
        RECT 3.200 -0.300 3.600 2.600 ;
    END
  END gnd
  PIN Y
    DIRECTION OUTPUT TRISTATE ;
    PORT
      LAYER metal1 ;
        RECT 1.900 0.600 2.300 2.600 ;
        RECT 1.900 5.400 2.300 9.400 ;
        RECT 2.000 0.600 2.300 9.400 ;
        RECT 1.800 4.300 2.300 4.700 ;
    END
  END Y
  PIN vdd
    DIRECTION INOUT ;
    USE POWER ;
    SHAPE ABUTMENT ;
    PORT
      LAYER metal1 ;
        RECT 0.200 7.400 0.600 10.300 ;
        RECT -0.200 9.700 4.200 10.300 ;
        RECT 3.200 5.400 3.600 10.300 ;
    END
  END vdd
  OBS 
      LAYER metal1 ;
        RECT 1.000 0.600 1.400 1.600 ;
        RECT 1.300 3.300 1.700 3.700 ;
        RECT 1.300 1.200 1.600 4.000 ;
        RECT 1.200 3.700 1.500 5.300 ;
        RECT 1.300 5.000 1.600 7.700 ;
        RECT 1.000 7.400 1.400 9.400 ;
  END 
END TBUFX1

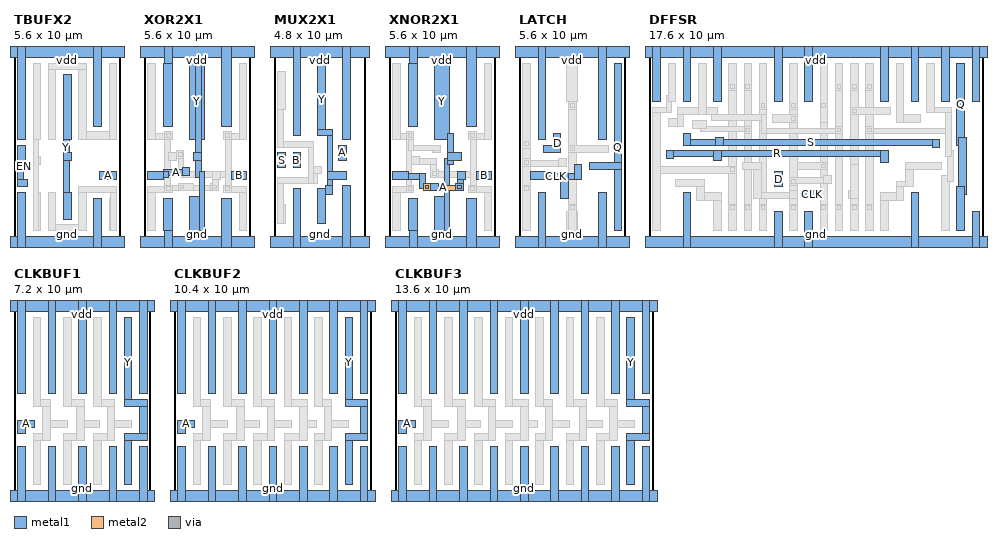
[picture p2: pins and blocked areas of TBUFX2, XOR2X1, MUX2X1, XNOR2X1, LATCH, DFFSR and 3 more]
MACRO TBUFX2
  CLASS  CORE ;
  FOREIGN TBUFX2 0.000 0.000 ;
  ORIGIN 0.000 0.000 ;
  SIZE 5.600 BY 10.000 ;
  SYMMETRY X Y  ;
  SITE core ;
  PIN A
    DIRECTION INPUT ;
    PORT
      LAYER metal1 ;
        RECT 4.500 3.300 5.400 3.700 ;
    END
  END A
  PIN EN
    DIRECTION INPUT ;
    PORT
      LAYER metal1 ;
        RECT 0.200 2.900 0.500 5.100 ;
        RECT 0.200 2.900 0.700 3.300 ;
        RECT 0.200 4.300 0.600 5.100 ;
    END
  END EN
  PIN gnd
    DIRECTION INOUT ;
    USE GROUND ;
    SHAPE ABUTMENT ;
    PORT
      LAYER metal1 ;
        RECT 0.200 -0.300 0.600 2.600 ;
        RECT -0.200 -0.300 5.800 0.300 ;
        RECT 4.200 -0.300 4.600 2.300 ;
    END
  END gnd
  PIN Y
    DIRECTION OUTPUT TRISTATE ;
    PORT
      LAYER metal1 ;
        RECT 2.600 1.200 2.900 8.800 ;
        RECT 2.600 5.400 3.000 8.800 ;
        RECT 2.600 4.300 3.000 4.700 ;
        RECT 2.600 1.200 3.000 2.600 ;
    END
  END Y
  PIN vdd
    DIRECTION INOUT ;
    USE POWER ;
    SHAPE ABUTMENT ;
    PORT
      LAYER metal1 ;
        RECT 0.200 5.400 0.600 10.300 ;
        RECT -0.200 9.700 5.800 10.300 ;
        RECT 4.200 6.100 4.600 10.300 ;
    END
  END vdd
  OBS 
      LAYER metal1 ;
        RECT 1.000 0.600 1.400 2.600 ;
        RECT 1.000 4.100 1.400 4.500 ;
        RECT 1.000 0.600 1.300 9.400 ;
        RECT 1.000 5.400 1.400 9.400 ;
        RECT 3.400 5.400 5.400 5.800 ;
        RECT 1.800 5.400 2.200 9.400 ;
        RECT 3.400 5.400 3.800 9.400 ;
        RECT 1.800 9.100 3.800 9.400 ;
        RECT 5.000 5.400 5.400 9.400 ;
        RECT 1.800 0.600 3.800 0.900 ;
        RECT 5.000 0.600 5.400 2.300 ;
        RECT 3.400 0.600 3.800 2.900 ;
        RECT 1.800 0.600 2.200 2.600 ;
        RECT 5.100 0.600 5.400 2.900 ;
        RECT 3.400 2.600 5.400 2.900 ;
  END 
END TBUFX2

MACRO XOR2X1
  CLASS  CORE ;
  FOREIGN XOR2X1 0.000 0.000 ;
  ORIGIN 0.000 0.000 ;
  SIZE 5.600 BY 10.000 ;
  SYMMETRY X Y  ;
  SITE core ;
  PIN A
    DIRECTION INPUT ;
    PORT
      LAYER metal1 ;
        RECT 0.200 3.300 1.000 3.700 ;
        RECT 2.000 3.500 2.400 3.900 ;
        RECT 1.000 3.500 2.400 3.800 ;
        RECT 0.200 3.400 1.300 3.700 ;
    END
  END A
  PIN B
    DIRECTION INPUT ;
    PORT
      LAYER metal1 ;
        RECT 4.600 3.300 5.400 3.700 ;
    END
  END B
  PIN gnd
    DIRECTION INOUT ;
    USE GROUND ;
    SHAPE ABUTMENT ;
    PORT
      LAYER metal1 ;
        RECT 1.100 -0.300 1.500 2.300 ;
        RECT -0.200 -0.300 5.800 0.300 ;
        RECT 4.100 -0.300 4.600 2.300 ;
        RECT 1.000 0.600 1.500 2.300 ;
    END
  END gnd
  PIN Y
    DIRECTION OUTPUT ;
    PORT
      LAYER metal1 ;
        RECT 2.600 4.300 3.000 4.700 ;
        RECT 2.400 5.400 3.200 9.400 ;
        RECT 2.900 0.600 3.200 3.700 ;
        RECT 2.700 3.400 3.000 9.400 ;
        RECT 2.400 0.600 3.200 2.400 ;
    END
  END Y
  PIN vdd
    DIRECTION INOUT ;
    USE POWER ;
    SHAPE ABUTMENT ;
    PORT
      LAYER metal1 ;
        RECT 1.000 6.100 1.500 9.400 ;
        RECT -0.200 9.700 5.800 10.300 ;
        RECT 4.100 6.100 4.600 10.300 ;
        RECT 1.100 6.100 1.500 10.300 ;
    END
  END vdd
  OBS 
      LAYER metal2 ;
        RECT 1.100 2.600 1.500 3.000 ;
        RECT 1.100 2.700 3.900 3.000 ;
        RECT 1.800 2.700 2.200 3.100 ;
        RECT 3.500 2.700 3.900 3.100 ;
        RECT 1.100 2.600 1.400 5.800 ;
        RECT 1.100 5.400 1.500 5.800 ;
        RECT 4.200 2.600 4.600 3.000 ;
        RECT 1.800 3.400 4.600 3.700 ;
        RECT 1.800 3.400 2.100 4.800 ;
        RECT 1.700 4.400 2.100 4.800 ;
        RECT 4.300 2.600 4.600 5.800 ;
        RECT 4.200 5.400 4.600 5.800 ;
      LAYER metal1 ;
        RECT 0.200 5.400 1.500 5.700 ;
        RECT 1.100 5.400 1.500 5.800 ;
        RECT 0.200 5.400 0.600 9.400 ;
        RECT 0.200 0.600 0.600 2.900 ;
        RECT 0.200 2.600 1.500 2.900 ;
        RECT 1.100 2.600 1.500 3.000 ;
        RECT 1.300 4.300 1.700 4.700 ;
        RECT 1.700 4.400 2.100 4.800 ;
        RECT 1.800 2.700 2.600 3.100 ;
        RECT 3.500 2.700 3.900 3.100 ;
        RECT 3.600 2.700 3.900 3.700 ;
        RECT 3.600 3.300 4.000 3.700 ;
        RECT 4.200 5.400 5.400 5.700 ;
        RECT 4.200 5.400 4.600 5.800 ;
        RECT 5.000 5.400 5.400 9.400 ;
        RECT 5.000 0.600 5.400 2.900 ;
        RECT 4.200 2.600 5.400 2.900 ;
        RECT 4.200 2.600 4.600 3.000 ;
      LAYER via ;
        RECT 1.200 5.500 1.400 5.700 ;
        RECT 1.200 2.700 1.400 2.900 ;
        RECT 1.800 4.500 2.000 4.700 ;
        RECT 1.900 2.800 2.100 3.000 ;
        RECT 3.600 2.800 3.800 3.000 ;
        RECT 4.300 5.500 4.500 5.700 ;
        RECT 4.300 2.700 4.500 2.900 ;
  END 
END XOR2X1

MACRO MUX2X1
  CLASS  CORE ;
  FOREIGN MUX2X1 0.000 0.000 ;
  ORIGIN 0.000 0.000 ;
  SIZE 4.800 BY 10.000 ;
  SYMMETRY X Y  ;
  SITE core ;
  PIN A
    DIRECTION INPUT ;
    PORT
      LAYER metal1 ;
        RECT 3.400 4.300 3.800 5.100 ;
    END
  END A
  PIN B
    DIRECTION INPUT ;
    PORT
      LAYER metal1 ;
        RECT 1.000 3.900 1.400 4.700 ;
    END
  END B
  PIN S
    DIRECTION INPUT ;
    PORT
      LAYER metal1 ;
        RECT 0.200 3.900 0.600 4.700 ;
    END
  END S
  PIN gnd
    DIRECTION INOUT ;
    USE GROUND ;
    SHAPE ABUTMENT ;
    PORT
      LAYER metal1 ;
        RECT 1.000 -0.300 1.400 2.800 ;
        RECT -0.200 -0.300 5.000 0.300 ;
        RECT 3.600 -0.300 4.000 3.000 ;
    END
  END gnd
  PIN Y
    DIRECTION OUTPUT ;
    PORT
      LAYER metal1 ;
        RECT 2.300 1.000 2.700 2.800 ;
        RECT 2.800 3.300 3.800 3.700 ;
        RECT 2.300 5.600 3.100 5.900 ;
        RECT 2.800 2.500 3.100 5.900 ;
        RECT 2.700 2.500 3.100 3.000 ;
        RECT 2.300 5.600 2.700 9.400 ;
    END
  END Y
  PIN vdd
    DIRECTION INOUT ;
    USE POWER ;
    SHAPE ABUTMENT ;
    PORT
      LAYER metal1 ;
        RECT 1.000 5.600 1.400 10.300 ;
        RECT -0.200 9.700 5.000 10.300 ;
        RECT 3.600 5.400 4.000 10.300 ;
    END
  END vdd
  OBS 
      LAYER metal1 ;
        RECT 0.200 1.000 0.600 2.000 ;
        RECT 0.200 1.000 0.500 3.400 ;
        RECT 0.200 3.100 2.300 3.400 ;
        RECT 1.800 3.100 2.300 4.000 ;
        RECT 1.800 3.600 2.500 4.000 ;
        RECT 1.800 3.100 2.100 5.300 ;
        RECT 0.200 5.000 2.100 5.300 ;
        RECT 0.200 5.000 0.500 9.000 ;
        RECT 0.200 7.000 0.600 9.000 ;
  END 
END MUX2X1

MACRO XNOR2X1
  CLASS  CORE ;
  FOREIGN XNOR2X1 0.000 0.000 ;
  ORIGIN 0.000 0.000 ;
  SIZE 5.600 BY 10.000 ;
  SYMMETRY X Y  ;
  SITE core ;
  PIN A
    DIRECTION INPUT ;
    PORT
      LAYER metal2 ;
        RECT 1.800 2.700 2.200 3.100 ;
        RECT 3.500 2.700 3.900 3.100 ;
        RECT 1.800 2.700 3.900 3.000 ;
      LAYER via ;
        RECT 1.900 2.800 2.100 3.000 ;
        RECT 3.600 2.800 3.800 3.000 ;
      LAYER metal1 ;
        RECT 0.200 3.300 1.000 3.700 ;
        RECT 3.600 3.300 4.000 3.700 ;
        RECT 3.600 2.700 3.900 3.700 ;
        RECT 3.500 2.700 3.900 3.100 ;
        RECT 1.800 2.700 2.600 3.100 ;
        RECT 0.200 3.300 1.900 3.600 ;
        RECT 1.600 2.800 1.900 3.600 ;
    END
  END A
  PIN B
    DIRECTION INPUT ;
    PORT
      LAYER metal1 ;
        RECT 4.600 3.300 5.400 3.700 ;
    END
  END B
  PIN gnd
    DIRECTION INOUT ;
    USE GROUND ;
    SHAPE ABUTMENT ;
    PORT
      LAYER metal1 ;
        RECT 1.100 -0.300 1.500 2.300 ;
        RECT -0.200 -0.300 5.800 0.300 ;
        RECT 4.100 -0.300 4.600 2.300 ;
        RECT 1.000 0.600 1.500 2.300 ;
    END
  END gnd
  PIN Y
    DIRECTION OUTPUT ;
    PORT
      LAYER metal1 ;
        RECT 2.400 0.600 3.200 2.400 ;
        RECT 3.100 4.300 3.800 4.700 ;
        RECT 3.100 4.100 3.400 5.700 ;
        RECT 2.400 5.400 3.200 9.400 ;
        RECT 2.900 0.600 3.200 4.400 ;
    END
  END Y
  PIN vdd
    DIRECTION INOUT ;
    USE POWER ;
    SHAPE ABUTMENT ;
    PORT
      LAYER metal1 ;
        RECT 1.000 6.100 1.500 9.400 ;
        RECT -0.200 9.700 5.800 10.300 ;
        RECT 4.100 6.100 4.600 10.300 ;
        RECT 1.100 6.100 1.500 10.300 ;
    END
  END vdd
  OBS 
      LAYER metal2 ;
        RECT 0.900 2.600 1.300 3.000 ;
        RECT 0.900 2.600 1.200 5.800 ;
        RECT 0.900 5.400 1.300 5.800 ;
        RECT 4.200 2.600 4.600 3.000 ;
        RECT 2.200 3.400 4.600 3.700 ;
        RECT 2.200 3.400 2.600 3.800 ;
        RECT 4.300 2.600 4.600 5.800 ;
        RECT 4.200 5.400 4.600 5.800 ;
      LAYER metal1 ;
        RECT 0.200 0.600 0.600 2.900 ;
        RECT 0.200 2.600 1.300 2.900 ;
        RECT 0.900 2.600 1.300 3.000 ;
        RECT 2.200 3.400 2.600 3.800 ;
        RECT 2.200 3.400 2.500 4.400 ;
        RECT 1.200 4.100 2.500 4.400 ;
        RECT 1.200 4.100 1.600 4.500 ;
        RECT 2.300 4.700 2.700 5.100 ;
        RECT 1.000 4.800 2.700 5.100 ;
        RECT 0.200 5.400 1.300 5.700 ;
        RECT 1.000 4.800 1.300 5.800 ;
        RECT 0.900 5.400 1.300 5.800 ;
        RECT 0.200 5.400 0.600 9.400 ;
        RECT 4.200 5.400 5.400 5.700 ;
        RECT 4.200 5.400 4.600 5.800 ;
        RECT 5.000 5.400 5.400 9.400 ;
        RECT 5.000 0.600 5.400 2.900 ;
        RECT 4.200 2.600 5.400 2.900 ;
        RECT 4.200 2.600 4.600 3.000 ;
      LAYER via ;
        RECT 1.000 5.500 1.200 5.700 ;
        RECT 1.000 2.700 1.200 2.900 ;
        RECT 2.300 3.500 2.500 3.700 ;
        RECT 4.300 5.500 4.500 5.700 ;
        RECT 4.300 2.700 4.500 2.900 ;
  END 
END XNOR2X1

MACRO LATCH
  CLASS  CORE ;
  FOREIGN LATCH 0.000 0.000 ;
  ORIGIN 0.000 0.000 ;
  SIZE 5.600 BY 10.000 ;
  SYMMETRY X Y  ;
  SITE core ;
  PIN Q
    DIRECTION OUTPUT ;
    PORT
      LAYER metal1 ;
        RECT 3.700 3.800 5.400 4.200 ;
        RECT 5.000 0.600 5.400 9.400 ;
    END
  END Q
  PIN CLK
    DIRECTION INPUT ;
    USE CLOCK ;
    PORT
      LAYER metal1 ;
        RECT 0.600 3.300 1.400 3.700 ;
        RECT 2.900 3.300 3.300 4.100 ;
        RECT 0.600 3.300 3.300 3.600 ;
        RECT 2.200 2.300 2.600 3.600 ;
    END
  END CLK
  PIN D
    DIRECTION INPUT ;
    PORT
      LAYER metal1 ;
        RECT 1.300 4.700 2.200 5.100 ;
        RECT 1.800 4.700 2.200 5.700 ;
    END
  END D
  PIN gnd
    DIRECTION INOUT ;
    USE GROUND ;
    SHAPE ABUTMENT ;
    PORT
      LAYER metal1 ;
        RECT 1.000 -0.300 1.400 2.600 ;
        RECT -0.200 -0.300 5.800 0.300 ;
        RECT 4.200 -0.300 4.600 2.600 ;
    END
  END gnd
  PIN vdd
    DIRECTION INOUT ;
    USE POWER ;
    SHAPE ABUTMENT ;
    PORT
      LAYER metal1 ;
        RECT 1.000 5.400 1.400 10.300 ;
        RECT -0.200 9.700 5.800 10.300 ;
        RECT 4.200 5.400 4.600 10.300 ;
    END
  END vdd
  OBS 
      LAYER metal2 ;
        RECT 0.200 2.600 0.600 5.400 ;
        RECT 2.600 1.600 3.000 7.400 ;
      LAYER metal1 ;
        RECT 0.200 4.900 0.600 9.400 ;
        RECT 0.200 0.600 0.600 3.000 ;
        RECT 0.200 4.000 2.500 4.300 ;
        RECT 0.200 4.000 0.600 4.400 ;
        RECT 2.100 4.000 2.500 4.400 ;
        RECT 2.600 7.000 3.000 9.400 ;
        RECT 2.500 7.400 3.100 9.400 ;
        RECT 2.500 0.600 3.100 1.600 ;
        RECT 2.600 0.600 3.000 2.000 ;
        RECT 2.600 4.700 4.700 5.100 ;
      LAYER via ;
        RECT 0.300 5.100 0.500 5.300 ;
        RECT 0.300 4.100 0.500 4.300 ;
        RECT 0.300 2.700 0.500 2.900 ;
        RECT 2.700 7.100 2.900 7.300 ;
        RECT 2.700 4.800 2.900 5.000 ;
        RECT 2.700 1.700 2.900 1.900 ;
  END 
END LATCH

MACRO DFFSR
  CLASS  CORE ;
  FOREIGN DFFSR 0.000 0.000 ;
  ORIGIN 0.000 0.000 ;
  SIZE 17.600 BY 10.000 ;
  SYMMETRY X Y  ;
  SITE core ;
  PIN Q
    DIRECTION OUTPUT ;
    PORT
      LAYER metal1 ;
        RECT 16.200 0.600 16.600 2.900 ;
        RECT 16.300 2.500 16.700 5.500 ;
        RECT 16.200 5.100 16.600 9.400 ;
    END
  END Q
  PIN CLK
    DIRECTION INPUT ;
    USE CLOCK ;
    PORT
      LAYER metal1 ;
        RECT 8.200 2.300 9.000 2.700 ;
    END
  END CLK
  PIN R
    DIRECTION INPUT ;
    PORT
      LAYER metal1 ;
        RECT 0.900 4.400 1.300 4.800 ;
        RECT 0.900 4.500 12.600 4.800 ;
        RECT 12.200 4.200 12.600 4.800 ;
        RECT 3.400 4.300 3.800 4.800 ;
    END
  END R
  PIN S
    DIRECTION INPUT ;
    PORT
      LAYER metal1 ;
        RECT 1.800 5.100 2.200 5.700 ;
        RECT 1.800 5.100 15.300 5.400 ;
        RECT 14.900 5.000 15.300 5.400 ;
        RECT 3.500 5.100 3.900 5.500 ;
    END
  END S
  PIN D
    DIRECTION INPUT ;
    PORT
      LAYER metal1 ;
        RECT 6.600 2.900 7.000 3.700 ;
    END
  END D
  PIN gnd
    DIRECTION INOUT ;
    USE GROUND ;
    SHAPE ABUTMENT ;
    PORT
      LAYER metal1 ;
        RECT 1.800 -0.300 2.200 2.600 ;
        RECT -0.200 -0.300 17.800 0.300 ;
        RECT 17.000 -0.300 17.400 1.600 ;
        RECT 13.800 -0.300 14.200 2.600 ;
        RECT 8.200 -0.300 8.600 1.600 ;
        RECT 6.600 -0.300 7.000 1.600 ;
    END
  END gnd
  PIN vdd
    DIRECTION INOUT ;
    USE POWER ;
    SHAPE ABUTMENT ;
    PORT
      LAYER metal1 ;
        RECT 0.200 7.400 0.600 10.300 ;
        RECT -0.200 9.700 17.800 10.300 ;
        RECT 17.000 7.400 17.400 10.300 ;
        RECT 15.400 7.400 15.800 10.300 ;
        RECT 13.800 7.400 14.200 10.300 ;
        RECT 12.200 7.400 12.600 10.300 ;
        RECT 8.200 7.400 8.600 10.300 ;
        RECT 6.600 7.400 7.000 10.300 ;
        RECT 3.400 7.400 3.800 10.300 ;
        RECT 1.800 7.400 2.200 10.300 ;
    END
  END vdd
  OBS 
      LAYER metal2 ;
        RECT 4.200 1.600 4.600 8.400 ;
        RECT 5.000 1.600 5.400 8.400 ;
        RECT 5.800 1.600 6.200 7.400 ;
        RECT 7.400 1.600 7.800 7.400 ;
        RECT 9.000 1.600 9.400 7.400 ;
        RECT 9.800 1.600 10.200 8.400 ;
        RECT 10.600 1.600 11.000 8.400 ;
        RECT 11.400 1.600 11.800 8.400 ;
      LAYER metal1 ;
        RECT 3.400 0.600 3.800 2.600 ;
        RECT 2.500 2.200 3.800 2.600 ;
        RECT 2.500 2.200 2.900 3.300 ;
        RECT 1.400 2.900 2.900 3.300 ;
        RECT 4.200 8.000 4.600 9.400 ;
        RECT 0.200 3.600 4.600 4.000 ;
        RECT 0.200 0.600 0.600 7.100 ;
        RECT 0.200 6.800 1.200 7.100 ;
        RECT 0.900 6.800 1.200 7.700 ;
        RECT 1.000 7.400 1.400 9.400 ;
        RECT 4.200 0.600 4.600 2.000 ;
        RECT 5.000 8.000 5.400 9.400 ;
        RECT 2.700 5.800 5.400 6.100 ;
        RECT 5.000 5.700 5.400 6.100 ;
        RECT 2.300 6.000 3.000 6.400 ;
        RECT 5.000 0.600 5.400 2.000 ;
        RECT 5.800 7.000 6.200 9.400 ;
        RECT 5.800 0.600 6.200 2.000 ;
        RECT 7.400 7.000 7.800 9.400 ;
        RECT 6.500 6.300 7.800 6.700 ;
        RECT 5.500 2.300 7.800 2.600 ;
        RECT 7.400 2.300 7.800 2.700 ;
        RECT 5.500 2.300 5.900 4.200 ;
        RECT 4.900 3.800 5.900 4.200 ;
        RECT 7.400 0.600 7.800 2.000 ;
        RECT 9.000 6.300 9.400 9.400 ;
        RECT 7.800 3.800 9.400 4.200 ;
        RECT 9.000 0.600 9.400 2.000 ;
        RECT 7.400 3.000 7.800 3.400 ;
        RECT 7.400 3.100 9.600 3.400 ;
        RECT 9.200 3.100 9.600 3.500 ;
        RECT 9.800 8.000 10.200 9.400 ;
        RECT 5.900 5.700 10.200 6.000 ;
        RECT 9.800 5.700 10.200 6.100 ;
        RECT 1.000 6.100 1.800 6.500 ;
        RECT 1.500 6.100 1.800 7.100 ;
        RECT 3.300 6.400 6.200 6.700 ;
        RECT 5.900 5.700 6.200 6.700 ;
        RECT 1.500 6.700 3.600 7.100 ;
        RECT 2.600 6.700 3.000 9.400 ;
        RECT 9.800 0.600 10.200 2.000 ;
        RECT 10.600 8.000 11.000 9.400 ;
        RECT 10.500 2.300 11.000 2.700 ;
        RECT 10.600 2.300 11.000 4.100 ;
        RECT 10.600 0.600 11.000 2.000 ;
        RECT 11.400 8.000 11.800 9.400 ;
        RECT 11.400 0.600 11.800 2.000 ;
        RECT 10.600 6.700 12.700 7.100 ;
        RECT 13.000 6.300 14.300 6.700 ;
        RECT 13.000 6.300 13.400 9.400 ;
        RECT 12.200 0.600 12.600 2.600 ;
        RECT 12.200 2.200 13.400 2.600 ;
        RECT 13.000 2.200 13.400 3.200 ;
        RECT 13.000 2.900 13.900 3.200 ;
        RECT 13.500 2.900 13.900 4.200 ;
        RECT 13.500 3.800 15.400 4.200 ;
        RECT 15.400 0.600 15.800 3.500 ;
        RECT 15.700 3.200 16.000 4.800 ;
        RECT 11.400 5.700 15.900 6.000 ;
        RECT 11.400 5.700 11.800 6.100 ;
        RECT 15.600 4.500 15.900 7.100 ;
        RECT 14.600 6.800 15.900 7.100 ;
        RECT 14.600 6.800 15.000 9.400 ;
      LAYER via ;
        RECT 4.300 8.100 4.500 8.300 ;
        RECT 4.300 3.700 4.500 3.900 ;
        RECT 4.300 1.700 4.500 1.900 ;
        RECT 5.100 8.100 5.300 8.300 ;
        RECT 5.100 5.800 5.300 6.000 ;
        RECT 5.100 1.700 5.300 1.900 ;
        RECT 5.900 7.100 6.100 7.300 ;
        RECT 5.900 1.700 6.100 1.900 ;
        RECT 7.500 7.100 7.700 7.300 ;
        RECT 7.500 6.400 7.700 6.600 ;
        RECT 7.500 3.100 7.700 3.300 ;
        RECT 7.500 1.700 7.700 1.900 ;
        RECT 9.100 7.100 9.300 7.300 ;
        RECT 9.100 3.900 9.300 4.100 ;
        RECT 9.100 1.700 9.300 1.900 ;
        RECT 9.900 8.100 10.100 8.300 ;
        RECT 9.900 5.800 10.100 6.000 ;
        RECT 9.900 1.700 10.100 1.900 ;
        RECT 10.700 8.100 10.900 8.300 ;
        RECT 10.700 6.800 10.900 7.000 ;
        RECT 10.700 1.700 10.900 1.900 ;
        RECT 11.500 8.100 11.700 8.300 ;
        RECT 11.500 5.800 11.700 6.000 ;
        RECT 11.500 1.700 11.700 1.900 ;
  END 
END DFFSR

MACRO CLKBUF1
  CLASS  CORE ;
  FOREIGN CLKBUF1 0.000 0.000 ;
  ORIGIN 0.000 0.000 ;
  SIZE 7.200 BY 10.000 ;
  SYMMETRY X Y  ;
  SITE core ;
  PIN A
    DIRECTION INPUT ;
    PORT
      LAYER metal1 ;
        RECT 0.200 3.300 0.600 4.000 ;
        RECT 0.200 3.600 1.100 4.000 ;
    END
  END A
  PIN gnd
    DIRECTION INOUT ;
    USE GROUND ;
    SHAPE ABUTMENT ;
    PORT
      LAYER metal1 ;
        RECT 0.200 -0.300 0.600 2.600 ;
        RECT -0.200 -0.300 7.400 0.300 ;
        RECT 6.600 -0.300 7.000 2.600 ;
        RECT 5.000 -0.300 5.400 2.600 ;
        RECT 3.400 -0.300 3.800 2.600 ;
        RECT 1.800 -0.300 2.200 2.600 ;
    END
  END gnd
  PIN Y
    DIRECTION OUTPUT ;
    PORT
      LAYER metal1 ;
        RECT 5.800 0.600 6.200 3.300 ;
        RECT 5.800 4.700 7.000 5.100 ;
        RECT 6.600 2.900 7.000 5.100 ;
        RECT 5.800 2.900 7.000 3.300 ;
        RECT 5.800 4.700 6.200 9.400 ;
    END
  END Y
  PIN vdd
    DIRECTION INOUT ;
    USE POWER ;
    SHAPE ABUTMENT ;
    PORT
      LAYER metal1 ;
        RECT 0.200 5.400 0.600 10.300 ;
        RECT -0.200 9.700 7.400 10.300 ;
        RECT 6.600 5.400 7.000 10.300 ;
        RECT 5.000 5.400 5.400 10.300 ;
        RECT 3.400 5.400 3.800 10.300 ;
        RECT 1.800 5.400 2.200 10.300 ;
    END
  END vdd
  OBS 
      LAYER metal1 ;
        RECT 1.000 0.600 1.400 3.300 ;
        RECT 1.000 2.900 1.900 3.300 ;
        RECT 1.500 3.600 2.800 4.000 ;
        RECT 1.500 2.900 1.900 5.100 ;
        RECT 1.000 4.700 1.900 5.100 ;
        RECT 1.000 4.700 1.400 9.400 ;
        RECT 2.600 0.600 3.000 3.300 ;
        RECT 2.600 2.900 3.700 3.300 ;
        RECT 3.300 3.600 4.500 4.000 ;
        RECT 3.300 2.900 3.700 5.100 ;
        RECT 2.600 4.700 3.700 5.100 ;
        RECT 2.600 4.700 3.000 9.400 ;
        RECT 4.200 0.600 4.600 3.300 ;
        RECT 4.200 2.900 5.300 3.300 ;
        RECT 4.900 3.600 6.200 4.000 ;
        RECT 4.900 2.900 5.300 5.100 ;
        RECT 4.200 4.700 5.300 5.100 ;
        RECT 4.200 4.700 4.600 9.400 ;
  END 
END CLKBUF1

MACRO CLKBUF2
  CLASS  CORE ;
  FOREIGN CLKBUF2 0.000 0.000 ;
  ORIGIN 0.000 0.000 ;
  SIZE 10.400 BY 10.000 ;
  SYMMETRY X Y  ;
  SITE core ;
  PIN A
    DIRECTION INPUT ;
    PORT
      LAYER metal1 ;
        RECT 0.200 3.300 0.600 4.000 ;
        RECT 0.200 3.600 1.100 4.000 ;
    END
  END A
  PIN gnd
    DIRECTION INOUT ;
    USE GROUND ;
    SHAPE ABUTMENT ;
    PORT
      LAYER metal1 ;
        RECT 0.200 -0.300 0.600 2.600 ;
        RECT -0.200 -0.300 10.600 0.300 ;
        RECT 9.800 -0.300 10.200 2.600 ;
        RECT 8.200 -0.300 8.600 2.600 ;
        RECT 6.600 -0.300 7.000 2.600 ;
        RECT 5.000 -0.300 5.400 2.600 ;
        RECT 3.400 -0.300 3.800 2.600 ;
        RECT 1.800 -0.300 2.200 2.600 ;
    END
  END gnd
  PIN Y
    DIRECTION OUTPUT ;
    PORT
      LAYER metal1 ;
        RECT 9.000 0.600 9.400 3.300 ;
        RECT 9.000 4.700 10.200 5.100 ;
        RECT 9.800 2.900 10.200 5.100 ;
        RECT 9.000 2.900 10.200 3.300 ;
        RECT 9.000 4.700 9.400 9.400 ;
    END
  END Y
  PIN vdd
    DIRECTION INOUT ;
    USE POWER ;
    SHAPE ABUTMENT ;
    PORT
      LAYER metal1 ;
        RECT 0.200 5.400 0.600 10.300 ;
        RECT -0.200 9.700 10.600 10.300 ;
        RECT 9.800 5.400 10.200 10.300 ;
        RECT 8.200 5.400 8.600 10.300 ;
        RECT 6.600 5.400 7.000 10.300 ;
        RECT 5.000 5.400 5.400 10.300 ;
        RECT 3.400 5.400 3.800 10.300 ;
        RECT 1.800 5.400 2.200 10.300 ;
    END
  END vdd
  OBS 
      LAYER metal1 ;
        RECT 1.000 0.600 1.400 3.300 ;
        RECT 1.000 2.900 1.900 3.300 ;
        RECT 1.500 3.600 2.800 4.000 ;
        RECT 1.500 2.900 1.900 5.100 ;
        RECT 1.000 4.700 1.900 5.100 ;
        RECT 1.000 4.700 1.400 9.400 ;
        RECT 2.600 0.600 3.000 3.300 ;
        RECT 2.600 2.900 3.700 3.300 ;
        RECT 3.300 3.600 4.500 4.000 ;
        RECT 3.300 2.900 3.700 5.100 ;
        RECT 2.600 4.700 3.700 5.100 ;
        RECT 2.600 4.700 3.000 9.400 ;
        RECT 4.200 0.600 4.600 3.300 ;
        RECT 4.200 2.900 5.300 3.300 ;
        RECT 4.900 3.600 6.200 4.000 ;
        RECT 4.900 2.900 5.300 5.100 ;
        RECT 4.200 4.700 5.300 5.100 ;
        RECT 4.200 4.700 4.600 9.400 ;
        RECT 5.800 0.600 6.200 3.300 ;
        RECT 5.800 2.900 7.000 3.300 ;
        RECT 6.600 3.600 7.500 4.000 ;
        RECT 6.600 2.900 7.000 5.100 ;
        RECT 5.800 4.700 7.000 5.100 ;
        RECT 5.800 4.700 6.200 9.400 ;
        RECT 7.400 0.600 7.800 3.300 ;
        RECT 7.400 2.900 8.300 3.300 ;
        RECT 7.900 3.600 9.200 4.000 ;
        RECT 7.900 2.900 8.300 5.100 ;
        RECT 7.400 4.700 8.300 5.100 ;
        RECT 7.400 4.700 7.800 9.400 ;
  END 
END CLKBUF2

MACRO CLKBUF3
  CLASS  CORE ;
  FOREIGN CLKBUF3 0.000 0.000 ;
  ORIGIN 0.000 0.000 ;
  SIZE 13.600 BY 10.000 ;
  SYMMETRY X Y  ;
  SITE core ;
  PIN A
    DIRECTION INPUT ;
    PORT
      LAYER metal1 ;
        RECT 0.200 3.300 0.600 4.000 ;
        RECT 0.200 3.600 1.100 4.000 ;
    END
  END A
  PIN gnd
    DIRECTION INOUT ;
    USE GROUND ;
    SHAPE ABUTMENT ;
    PORT
      LAYER metal1 ;
        RECT 0.200 -0.300 0.600 2.600 ;
        RECT -0.200 -0.300 13.800 0.300 ;
        RECT 13.000 -0.300 13.400 2.600 ;
        RECT 11.400 -0.300 11.800 2.600 ;
        RECT 9.800 -0.300 10.200 2.600 ;
        RECT 8.200 -0.300 8.600 2.600 ;
        RECT 6.600 -0.300 7.000 2.600 ;
        RECT 5.000 -0.300 5.400 2.600 ;
        RECT 3.400 -0.300 3.800 2.600 ;
        RECT 1.800 -0.300 2.200 2.600 ;
    END
  END gnd
  PIN Y
    DIRECTION OUTPUT ;
    PORT
      LAYER metal1 ;
        RECT 12.200 0.600 12.600 3.300 ;
        RECT 12.200 4.700 13.400 5.100 ;
        RECT 13.000 2.900 13.400 5.100 ;
        RECT 12.200 2.900 13.400 3.300 ;
        RECT 12.200 4.700 12.600 9.400 ;
    END
  END Y
  PIN vdd
    DIRECTION INOUT ;
    USE POWER ;
    SHAPE ABUTMENT ;
    PORT
      LAYER metal1 ;
        RECT 0.200 5.400 0.600 10.300 ;
        RECT -0.200 9.700 13.800 10.300 ;
        RECT 13.000 5.400 13.400 10.300 ;
        RECT 11.400 5.400 11.800 10.300 ;
        RECT 9.800 5.400 10.200 10.300 ;
        RECT 8.200 5.400 8.600 10.300 ;
        RECT 6.600 5.400 7.000 10.300 ;
        RECT 5.000 5.400 5.400 10.300 ;
        RECT 3.400 5.400 3.800 10.300 ;
        RECT 1.800 5.400 2.200 10.300 ;
    END
  END vdd
  OBS 
      LAYER metal1 ;
        RECT 1.000 0.600 1.400 3.300 ;
        RECT 1.000 2.900 1.900 3.300 ;
        RECT 1.500 3.600 2.800 4.000 ;
        RECT 1.500 2.900 1.900 5.100 ;
        RECT 1.000 4.700 1.900 5.100 ;
        RECT 1.000 4.700 1.400 9.400 ;
        RECT 2.600 0.600 3.000 3.300 ;
        RECT 2.600 2.900 3.700 3.300 ;
        RECT 3.300 3.600 4.500 4.000 ;
        RECT 3.300 2.900 3.700 5.100 ;
        RECT 2.600 4.700 3.700 5.100 ;
        RECT 2.600 4.700 3.000 9.400 ;
        RECT 4.200 0.600 4.600 3.300 ;
        RECT 4.200 2.900 5.300 3.300 ;
        RECT 4.900 3.600 6.200 4.000 ;
        RECT 4.900 2.900 5.300 5.100 ;
        RECT 4.200 4.700 5.300 5.100 ;
        RECT 4.200 4.700 4.600 9.400 ;
        RECT 5.800 0.600 6.200 3.300 ;
        RECT 5.800 2.900 7.000 3.300 ;
        RECT 6.600 3.600 7.500 4.000 ;
        RECT 6.600 2.900 7.000 5.100 ;
        RECT 5.800 4.700 7.000 5.100 ;
        RECT 5.800 4.700 6.200 9.400 ;
        RECT 7.400 0.600 7.800 3.300 ;
        RECT 7.400 2.900 8.300 3.300 ;
        RECT 7.900 3.600 9.200 4.000 ;
        RECT 7.900 2.900 8.300 5.100 ;
        RECT 7.400 4.700 8.300 5.100 ;
        RECT 7.400 4.700 7.800 9.400 ;
        RECT 9.000 0.600 9.400 3.300 ;
        RECT 9.000 2.900 10.100 3.300 ;
        RECT 9.700 3.600 10.900 4.000 ;
        RECT 9.700 2.900 10.100 5.100 ;
        RECT 9.000 4.700 10.100 5.100 ;
        RECT 9.000 4.700 9.400 9.400 ;
        RECT 10.600 0.600 11.000 3.300 ;
        RECT 10.600 2.900 11.700 3.300 ;
        RECT 11.300 3.600 12.600 4.000 ;
        RECT 11.300 2.900 11.700 5.100 ;
        RECT 10.600 4.700 11.700 5.100 ;
        RECT 10.600 4.700 11.000 9.400 ;
  END 
END CLKBUF3

END LIBRARY
